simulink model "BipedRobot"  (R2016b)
settings: Solver=ode15s  StartTime=0.0  StopTime=Tend  FixedStep=0.001  RelTol=1e-3  AbsTol=1e-4  EnableMultiTasking=on
PreLoadFcn:
  | BipedRobot_param
  | load walk_forward
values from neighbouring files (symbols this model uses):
  bn = 50    [BipedRobot_param.m]    (also in SimpleContact_param.m)
  bt = 50    [BipedRobot_param.m]    (also in SimpleContact_param.m)
  kn = 5000    [BipedRobot_param.m]    (also in SimpleContact_param.m)
  kt = 5000    [BipedRobot_param.m]    (also in SimpleContact_param.m)
  mu_d = 0.8    [BipedRobot_param.m]    (also in SimpleContact_param.m)
  mu_s = 2    [BipedRobot_param.m]    (also in SimpleContact_param.m)
  N = 100    [initialize_para.m]    (also in main.m = walk_para.N; walk_parameter.m = 5)
  s = robot_para.s    [kinematics_calc.m]    (also in plot_graph.m; robot_parameter.m = 40; robot_view.m)
  zvt = 1e-3    (= 0.001)    [BipedRobot_param.m]    (also in SimpleContact_param.m)
undefined symbols (not defined in the file or in its folder): deg, Inertia, kg, m, Mass
libraries: mblibv1 x89, simulink x1
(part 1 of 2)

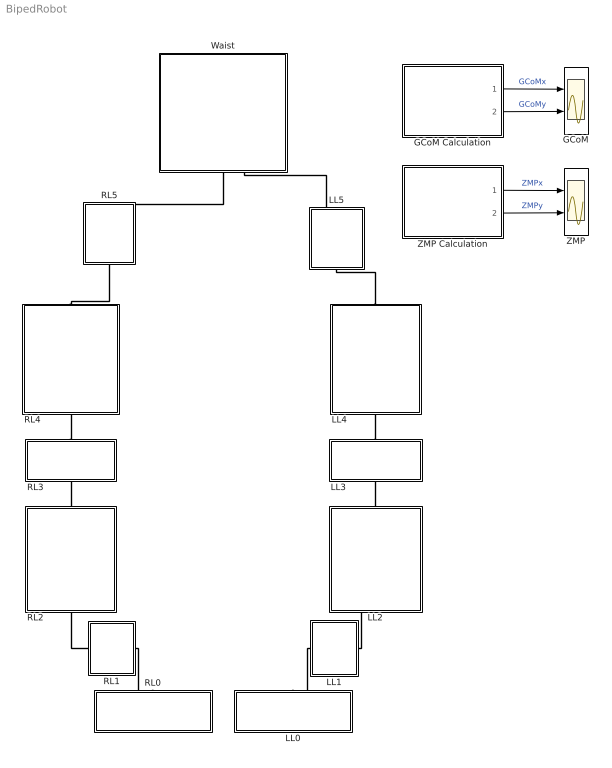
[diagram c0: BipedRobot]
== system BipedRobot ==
  GCoM : Scope  NumInputPorts=2
  GCoM Calculation : Subsystem
  LL0 : Subsystem
  LL1 : Subsystem
  LL2 : Subsystem
  LL3 : Subsystem
  LL4 : Subsystem
  LL5 : Subsystem
  RL0 : Subsystem
  RL1 : Subsystem
  RL2 : Subsystem
  RL3 : Subsystem
  RL4 : Subsystem
  RL5 : Subsystem
  Waist : Subsystem
  ZMP : Scope  NumInputPorts=2
  ZMP Calculation : Subsystem
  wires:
  GCoM Calculation/1(GCoMx) -> GCoM/1  "GCoMx"
  GCoM Calculation/2(GCoMy) -> GCoM/2  "GCoMy"
  ZMP Calculation/1(ZMPx) -> ZMP/1  "ZMPx"
  ZMP Calculation/2(ZMPy) -> ZMP/2  "ZMPy"
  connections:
  RL1/LConn1 -- RL0/RConn1
  RL2/LConn1 -- RL1/RConn1
  RL3/LConn1 -- RL2/RConn1
  Waist/LConn1 -- RL5/RConn1
  LL3/RConn1 -- LL4/LConn1
  LL2/RConn1 -- LL3/LConn1
  LL1/RConn1 -- LL2/LConn1
  LL1/LConn1 -- LL0/RConn1
  RL3/RConn1 -- RL4/LConn1
  RL4/RConn1 -- RL5/LConn1
  Waist/LConn2 -- LL5/RConn1
  LL5/LConn1 -- LL4/RConn1

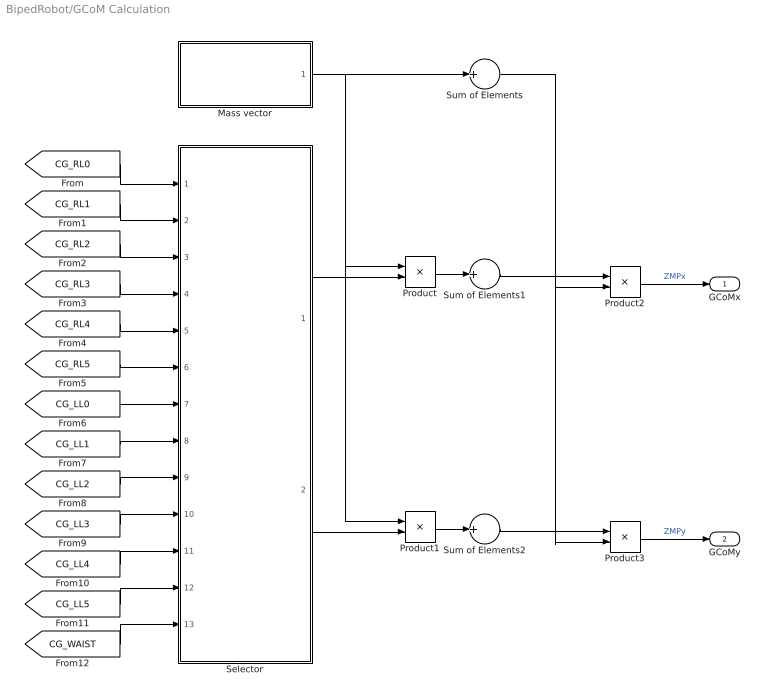
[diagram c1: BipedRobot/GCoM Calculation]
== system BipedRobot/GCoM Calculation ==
  Mass vector : Subsystem
  Product : Product
  Product1 : Product
  Product2 : Product  Inputs=*/
  Product3 : Product  Inputs=*/
  Selector : Subsystem
  Sum of Elements : Sum  Inputs=+
  Sum of Elements1 : Sum  Inputs=+
  Sum of Elements2 : Sum  Inputs=+
  GCoMx : Outport
  GCoMy : Outport  Port=2
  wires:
  Product3/1 -> GCoMy/1  "ZMPy"
  Product2/1 -> GCoMx/1  "ZMPx"
  Product1/1 -> Sum of Elements2/1
  Product/1 -> Sum of Elements1/1
  [CG_RL0] -> Selector/1(CG_RL0)
  [CG_RL1] -> Selector/2(CG_RL1)
  [CG_RL2] -> Selector/3(CG_RL2)
  [CG_RL3] -> Selector/4(CG_RL3)
  [CG_RL4] -> Selector/5(CG_RL4)
  [CG_RL5] -> Selector/6(CG_RL5)
  [CG_LL0] -> Selector/7(CG_LL0)
  [CG_LL1] -> Selector/8(CG_LL1)
  [CG_LL2] -> Selector/9(CG_LL2)
  [CG_LL3] -> Selector/10(CG_LL3)
  [CG_LL4] -> Selector/11(CG_LL4)
  [CG_LL5] -> Selector/12(CG_LL5)
  [CG_WAIST] -> Selector/13(CG_WAIST)
  Selector/2(yvec) -> Product1/2
  Selector/1(xvec) -> Product/2
  Mass vector/1(Mvec) -> Product/1, Product1/1, Sum of Elements/1
  Sum of Elements1/1 -> Product2/1
  Sum of Elements2/1 -> Product3/1
  Sum of Elements/1 -> Product2/2, Product3/2

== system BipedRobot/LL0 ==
  Body : mblibv1/Bodies/Body  LConnTagsString=CS3|CS4|CS5|CS6  RConnTagsString=CG|CS2  UpdateFromCAD=off  DialogClass=MechanicalBodyBlock  Mass=Mass.LL0  MassUnits=kg  InertiaUnits=kg*m^2  Inertia=Inertia.LL0  Shape=Cylinder  ShapeDims=[1 1]  ShapeUnits=m  ShapeUse=false  Density=1  DensityUnits=kg/m^3  DensityUse=false  GraphicsMode=MACHINE_DEFAULT  BodyColorSelMode=MACHINE_DEFAULT  BodyColor=[1;0;0]  AttachedToCS=CG  CG=Right$CG$[7.96 5.62 -13.41]$CS1$CS1$mm$[0 0 0]$Euler X-Y-Z$deg$WORLD$true  WorkingFrames=Left$CS1$[0 20 40]$WORLD$WORLD$mm$[0 0 0]$Euler X-Y-Z$deg$WORLD$false#Right$CS2$[0 0 0]$CS1$CS1$mm$[0 0 0]$Euler X-Y-Z$deg$WORLD$true#Left$CS3$[65 -12.5 -40]$CS1$CS1$mm$[0 0 0]$Euler X-Y-Z$deg$WORLD$true#Left$CS4$[-30 -12.5 -40]$CS1$CS1$mm$[0 0 0]$Euler X-Y-Z$deg$WORLD$true#Left$CS5$[65 52.5 -40]$CS1$CS1$mm$[0 0 0]$Euler X-Y-Z$deg$WORLD$true#Left$CS6$[-30 52.5 -40]$CS1$CS1$mm$[0 0 0]$Euler X-Y-Z$d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  CGPos=[7.96 5.62 -13.41]  CGRot=[0 0 0]  CS0Pos=[]  CS0Rot=[]  CS1Pos=[0 20 40]  CS1Rot=[0 0 0]  CS2Pos=[0 0 0]  CS2Rot=[0 0 0]  CS3Pos=[65 -12.5 -40]  CS3Rot=[0 0 0]  CS4Pos=[-30 -12.5 -40]  CS4Rot=[0 0 0]  CS5Pos=[65 52.5 -40]  CS5Rot=[0 0 0]  CS6Pos=[-30 52.5 -40]  CS6Rot=[0 0 0]  CS7Pos=[]  CS7Rot=[]  CS8Pos=[]  CS8Rot=[]  CS9Pos=[]  CS9Rot=[]  CS10Pos=[]  CS10Rot=[]  CS11Pos=[]  CS11Rot=[]  CS12Pos=[]  CS12Rot=[]  CS13Pos=[]  CS13Rot=[]  CS14Pos=[]  CS14Rot=[]  CS15Pos=[]  CS15Rot=[]  CS16Pos=[]  CS16Rot=[]  CS17Pos=[]  CS17Rot=[]  CS18Pos=[]  CS18Rot=[]  CS19Pos=[]  CS19Rot=[]  CS20Pos=[]  CS20Rot=[]
  Body Sensor : mblibv1/Sensors &  Actuators/Body Sensor  UpdateFromCAD=off  PhysicalDomain=Mechanical  PortType=blob  Muxed=off  Pose=off  Angle=on  AngleUnits=deg  ArcVelocity=off  ArcVelocityUnits=deg/s  ArcAcceleration=off  ArcAccelerationUnits=deg/s^2  CoordPosition=on  CoordPositionUnits=m  Velocity=off  VelocityUnits=m/s  Acceleration=off  AccelerationUnits=m/s^2  Quaternion=on  QuaternionDT=off  QuaternionDDT=off  QuaternionUnits=off  OutputVector=[1]  ActiveIO=on  Width=3  DialogClass=MechanicalSensorBlock  ReferenceFrame=Absolute (World)
  Contact1 : Subsystem
  Contact2 : Subsystem
  Contact3 : Subsystem
  Contact4 : Subsystem
  From Workspace : FromWorkspace  VariableName=Motion.LL0  SampleTime=0
  Joint Actuator : mblibv1/Sensors &  Actuators/Joint Actuator  UpdateFromCAD=off  PhysicalDomain=Mechanical  PortType=blob  ActuationStyle=Motion  AngleUnits=deg  ArcVelocityUnits=deg/s  ArcAccelerationUnits=deg/s^2  CoordPositionUnits=m  VelocityUnits=m/s  AccelerationUnits=m/s^2  ForceUnits=N  TorqueUnits=N-m  ActiveIO=on  Width=3  DialogClass=MechanicalActuatorBlock  Primitive=R1  ReferenceFrame=Absolute (INERTIAL)
  Mechanical Branching Bar : mblibv1/Utilities/Mechanical Branching Bar  LConnTagsString=_newl0  RConnTagsString=SA0|SA1  UpdateFromCAD=off  DialogClass=MechanicalBranchingBarBlock  NumSAPorts=2
  Revolute : mblibv1/Joints/Revolute  LConnTagsString=__newl0|SA1  RConnTagsString=__newr0  UpdateFromCAD=off  NumSAPorts=1  CutJoint=off  MarkAsCut=off  Primitives=revolute  PrimitiveProps=R1$World$[1 0 0]$revolute  DialogClass=JointBlock  R1Axis=[1 0 0]
  C1 : PMIOPort  Port=1  Side=Right
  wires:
  From Workspace/1 -> Joint Actuator/1
  Body Sensor/1 -> [CG_LL0]
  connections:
  Contact1/RConn1 -- Body/LConn1
  Contact2/RConn1 -- Body/LConn2
  Contact3/RConn1 -- Body/LConn3
  Contact4/RConn1 -- Body/LConn4
  C1/RConn1 -- Revolute/RConn1
  Mechanical Branching Bar/LConn1 -- Revolute/LConn2
  Joint Actuator/RConn1 -- Mechanical Branching Bar/RConn1
  Revolute/LConn1 -- Body/RConn2
  Body Sensor/LConn1 -- Body/RConn1

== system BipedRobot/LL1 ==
  Body : mblibv1/Bodies/Body  LConnTagsString=CG|CS1  RConnTagsString=CS2  UpdateFromCAD=off  DialogClass=MechanicalBodyBlock  Mass=Mass.LL1  MassUnits=kg  InertiaUnits=kg*m^2  Inertia=Inertia.LL1  Shape=Cylinder  ShapeDims=[1 1]  ShapeUnits=m  ShapeUse=false  Density=1  DensityUnits=kg/m^3  DensityUse=false  GraphicsMode=MACHINE_DEFAULT  BodyColorSelMode=MACHINE_DEFAULT  BodyColor=[1;0;0]  AttachedToCS=CG  CG=Left$CG$[-6.4 13.1 0]$CS1$CS1$mm$[0 0 0]$Euler X-Y-Z$deg$WORLD$true  WorkingFrames=Left$CS1$[0 20 40]$WORLD$WORLD$mm$[0 0 0]$Euler X-Y-Z$deg$WORLD$true#Right$CS2$[0 0 0]$CS1$CS1$mm$[0 0 0]$Euler X-Y-Z$deg$WORLD$true  CGPos=[-6.4 13.1 0]  CGRot=[0 0 0]  CS0Pos=[]  CS0Rot=[]  CS1Pos=[0 20 40]  CS1Rot=[0 0 0]  CS2Pos=[0 0 0]  CS2Rot=[0 0 0]  CS3Pos=[]  CS3Rot=[]  CS4Pos=[]  CS4Rot=[]  CS5Pos=[]  CS5Rot=[]  CS6Pos=[]  CS6Rot=[]  CS7Pos=[]  CS7Rot=[]  CS8Pos=[]  CS8Rot=[]  CS9Pos=[]  CS9Rot=[]  CS10Pos=[]  CS10Rot=[]  CS11Pos=[]  CS11Rot=[]  CS12Pos=[]  CS12Rot=[]  CS13Pos=[]  CS13Rot=[]  CS14Pos=[]  CS14Rot=[]  CS15Pos=[]  CS15Rot=[]  CS16Pos=[]  CS16Rot=[]  CS17Pos=[]  CS17Rot=[]  CS18Pos=[]  CS18Rot=[]  CS19Pos=[]  CS19Rot=[]  CS20Pos=[]  CS20Rot=[]
  Body Sensor : mblibv1/Sensors &  Actuators/Body Sensor  UpdateFromCAD=off  PhysicalDomain=Mechanical  PortType=blob  Muxed=off  Pose=off  Angle=on  AngleUnits=deg  ArcVelocity=off  ArcVelocityUnits=deg/s  ArcAcceleration=off  ArcAccelerationUnits=deg/s^2  CoordPosition=on  CoordPositionUnits=m  Velocity=off  VelocityUnits=m/s  Acceleration=off  AccelerationUnits=m/s^2  Quaternion=on  QuaternionDT=off  QuaternionDDT=off  QuaternionUnits=off  OutputVector=[1]  ActiveIO=on  Width=3  DialogClass=MechanicalSensorBlock  ReferenceFrame=Absolute (World)
  From Workspace : FromWorkspace  VariableName=Motion.LL1  SampleTime=0
  Joint Actuator : mblibv1/Sensors &  Actuators/Joint Actuator  UpdateFromCAD=off  PhysicalDomain=Mechanical  PortType=blob  ActuationStyle=Motion  AngleUnits=deg  ArcVelocityUnits=deg/s  ArcAccelerationUnits=deg/s^2  CoordPositionUnits=m  VelocityUnits=m/s  AccelerationUnits=m/s^2  ForceUnits=N  TorqueUnits=N-m  ActiveIO=on  Width=3  DialogClass=MechanicalActuatorBlock  Primitive=R1  ReferenceFrame=Absolute (INERTIAL)
  Mechanical Branching Bar : mblibv1/Utilities/Mechanical Branching Bar  LConnTagsString=_newl0  RConnTagsString=SA0|SA1  UpdateFromCAD=off  DialogClass=MechanicalBranchingBarBlock  NumSAPorts=2
  Revolute : mblibv1/Joints/Revolute  LConnTagsString=__newl0|SA1  RConnTagsString=__newr0  UpdateFromCAD=off  NumSAPorts=1  CutJoint=off  MarkAsCut=off  Primitives=revolute  PrimitiveProps=R1$WORLD$[0 -1 0]$revolute  DialogClass=JointBlock  R1Axis=[0 -1 0]
  C1 : PMIOPort  Port=1  Side=Right
  C2 : PMIOPort  Port=2  Side=Left
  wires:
  From Workspace/1 -> Joint Actuator/1
  Body Sensor/1 -> [CG_LL1]
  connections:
  Body/LConn2 -- C2/RConn1
  Revolute/LConn1 -- Body/RConn1
  Revolute/RConn1 -- C1/RConn1
  Joint Actuator/RConn1 -- Mechanical Branching Bar/RConn1
  Mechanical Branching Bar/LConn1 -- Revolute/LConn2
  Body Sensor/LConn1 -- Body/LConn1

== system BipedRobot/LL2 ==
  Body : mblibv1/Bodies/Body  LConnTagsString=CG|CS1  RConnTagsString=CS2  UpdateFromCAD=off  DialogClass=MechanicalBodyBlock  Mass=Mass.LL2  MassUnits=kg  InertiaUnits=kg*m^2  Inertia=Inertia.LL2  Shape=Cylinder  ShapeDims=[1 1]  ShapeUnits=m  ShapeUse=false  Density=1  DensityUnits=kg/m^3  DensityUse=false  GraphicsMode=MACHINE_DEFAULT  BodyColorSelMode=MACHINE_DEFAULT  BodyColor=[1;0;0]  AttachedToCS=CG  CG=Left$CG$[10.55 32.59 38.17]$CS1$CS1$mm$[0 0 0]$Euler X-Y-Z$deg$WORLD$true  WorkingFrames=Left$CS1$[0 20 40]$WORLD$WORLD$mm$[0 0 0]$Euler X-Y-Z$deg$WORLD$true#Right$CS2$[0 0 85]$CS1$CS1$mm$[0 0 0]$Euler X-Y-Z$deg$WORLD$true  CGPos=[10.55 32.59 38.17]  CGRot=[0 0 0]  CS0Pos=[]  CS0Rot=[]  CS1Pos=[0 20 40]  CS1Rot=[0 0 0]  CS2Pos=[0 0 85]  CS2Rot=[0 0 0]  CS3Pos=[]  CS3Rot=[]  CS4Pos=[]  CS4Rot=[]  CS5Pos=[]  CS5Rot=[]  CS6Pos=[]  CS6Rot=[]  CS7Pos=[]  CS7Rot=[]  CS8Pos=[]  CS8Rot=[]  CS9Pos=[]  CS9Rot=[]  CS10Pos=[]  CS10Rot=[]  CS11Pos=[]  CS11Rot=[]  CS12Pos=[]  CS12Rot=[]  CS13Pos=[]  CS13Rot=[]  CS14Pos=[]  CS14Rot=[]  CS15Pos=[]  CS15Rot=[]  CS16Pos=[]  CS16Rot=[]  CS17Pos=[]  CS17Rot=[]  CS18Pos=[]  CS18Rot=[]  CS19Pos=[]  CS19Rot=[]  CS20Pos=[]  CS20Rot=[]
  Body Sensor : mblibv1/Sensors &  Actuators/Body Sensor  UpdateFromCAD=off  PhysicalDomain=Mechanical  PortType=blob  Muxed=off  Pose=off  Angle=on  AngleUnits=deg  ArcVelocity=off  ArcVelocityUnits=deg/s  ArcAcceleration=off  ArcAccelerationUnits=deg/s^2  CoordPosition=on  CoordPositionUnits=m  Velocity=off  VelocityUnits=m/s  Acceleration=off  AccelerationUnits=m/s^2  Quaternion=on  QuaternionDT=off  QuaternionDDT=off  QuaternionUnits=off  OutputVector=[1]  ActiveIO=on  Width=3  DialogClass=MechanicalSensorBlock  ReferenceFrame=Absolute (World)
  From Workspace : FromWorkspace  VariableName=Motion.LL2  SampleTime=0
  Joint Actuator : mblibv1/Sensors &  Actuators/Joint Actuator  UpdateFromCAD=off  PhysicalDomain=Mechanical  PortType=blob  ActuationStyle=Motion  AngleUnits=deg  ArcVelocityUnits=deg/s  ArcAccelerationUnits=deg/s^2  CoordPositionUnits=m  VelocityUnits=m/s  AccelerationUnits=m/s^2  ForceUnits=N  TorqueUnits=N-m  ActiveIO=on  Width=3  DialogClass=MechanicalActuatorBlock  Primitive=R1  ReferenceFrame=Absolute (INERTIAL)
  Mechanical Branching Bar : mblibv1/Utilities/Mechanical Branching Bar  LConnTagsString=_newl0  RConnTagsString=SA0|SA1  UpdateFromCAD=off  DialogClass=MechanicalBranchingBarBlock  NumSAPorts=2
  Revolute : mblibv1/Joints/Revolute  LConnTagsString=__newl0|SA1  RConnTagsString=__newr0  UpdateFromCAD=off  NumSAPorts=1  CutJoint=off  MarkAsCut=off  Primitives=revolute  PrimitiveProps=R1$WORLD$[0 -1 0]$revolute  DialogClass=JointBlock  R1Axis=[0 -1 0]
  C1 : PMIOPort  Port=1  Side=Right
  C2 : PMIOPort  Port=2  Side=Left
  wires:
  From Workspace/1 -> Joint Actuator/1
  Body Sensor/1 -> [CG_LL2]
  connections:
  Body/LConn2 -- C2/RConn1
  Body/RConn1 -- Revolute/LConn1
  Revolute/RConn1 -- C1/RConn1
  Joint Actuator/RConn1 -- Mechanical Branching Bar/RConn1
  Mechanical Branching Bar/LConn1 -- Revolute/LConn2
  Body Sensor/LConn1 -- Body/LConn1

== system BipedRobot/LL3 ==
  Body : mblibv1/Bodies/Body  LConnTagsString=CG|CS2  RConnTagsString=CS1  UpdateFromCAD=off  DialogClass=MechanicalBodyBlock  Mass=Mass.LL3  MassUnits=kg  InertiaUnits=kg*m^2  Inertia=Inertia.LL3  Shape=Cylinder  ShapeDims=[1 1]  ShapeUnits=m  ShapeUse=false  Density=1  DensityUnits=kg/m^3  DensityUse=false  GraphicsMode=MACHINE_DEFAULT  BodyColorSelMode=MACHINE_DEFAULT  BodyColor=[1;0;0]  AttachedToCS=CG  CG=Left$CG$[7.6 30.24 -48.36]$CS1$CS1$mm$[0 0 0]$Euler X-Y-Z$deg$WORLD$true  WorkingFrames=Right$CS1$[0 20 210]$WORLD$WORLD$mm$[0 0 0]$Euler X-Y-Z$deg$WORLD$true#Left$CS2$[0 0 -85]$CS1$CS1$mm$[0 0 0]$Euler X-Y-Z$deg$WORLD$true  CGPos=[7.6 30.24 -48.36]  CGRot=[0 0 0]  CS0Pos=[]  CS0Rot=[]  CS1Pos=[0 20 210]  CS1Rot=[0 0 0]  CS2Pos=[0 0 -85]  CS2Rot=[0 0 0]  CS3Pos=[]  CS3Rot=[]  CS4Pos=[]  CS4Rot=[]  CS5Pos=[]  CS5Rot=[]  CS6Pos=[]  CS6Rot=[]  CS7Pos=[]  CS7Rot=[]  CS8Pos=[]  CS8Rot=[]  CS9Pos=[]  CS9Rot=[]  CS10Pos=[]  CS10Rot=[]  CS11Pos=[]  CS11Rot=[]  CS12Pos=[]  CS12Rot=[]  CS13Pos=[]  CS13Rot=[]  CS14Pos=[]  CS14Rot=[]  CS15Pos=[]  CS15Rot=[]  CS16Pos=[]  CS16Rot=[]  CS17Pos=[]  CS17Rot=[]  CS18Pos=[]  CS18Rot=[]  CS19Pos=[]  CS19Rot=[]  CS20Pos=[]  CS20Rot=[]
  Body Sensor : mblibv1/Sensors &  Actuators/Body Sensor  UpdateFromCAD=off  PhysicalDomain=Mechanical  PortType=blob  Muxed=off  Pose=off  Angle=on  AngleUnits=deg  ArcVelocity=off  ArcVelocityUnits=deg/s  ArcAcceleration=off  ArcAccelerationUnits=deg/s^2  CoordPosition=on  CoordPositionUnits=m  Velocity=off  VelocityUnits=m/s  Acceleration=off  AccelerationUnits=m/s^2  Quaternion=on  QuaternionDT=off  QuaternionDDT=off  QuaternionUnits=off  OutputVector=[1]  ActiveIO=on  Width=3  DialogClass=MechanicalSensorBlock  ReferenceFrame=Absolute (World)
  From Workspace : FromWorkspace  VariableName=Motion.LL3  SampleTime=0
  Joint Actuator : mblibv1/Sensors &  Actuators/Joint Actuator  UpdateFromCAD=off  PhysicalDomain=Mechanical  PortType=blob  ActuationStyle=Motion  AngleUnits=deg  ArcVelocityUnits=deg/s  ArcAccelerationUnits=deg/s^2  CoordPositionUnits=m  VelocityUnits=m/s  AccelerationUnits=m/s^2  ForceUnits=N  TorqueUnits=N-m  ActiveIO=on  Width=3  DialogClass=MechanicalActuatorBlock  Primitive=R1  ReferenceFrame=Absolute (INERTIAL)
  Mechanical Branching Bar : mblibv1/Utilities/Mechanical Branching Bar  LConnTagsString=_newl0  RConnTagsString=SA0|SA1  UpdateFromCAD=off  DialogClass=MechanicalBranchingBarBlock  NumSAPorts=2
  Revolute : mblibv1/Joints/Revolute  LConnTagsString=__newl0|SA1  RConnTagsString=__newr0  UpdateFromCAD=off  NumSAPorts=1  CutJoint=off  MarkAsCut=off  Primitives=revolute  PrimitiveProps=R1$WORLD$[0 -1 0]$revolute  DialogClass=JointBlock  R1Axis=[0 -1 0]
  C1 : PMIOPort  Port=1  Side=Right
  C2 : PMIOPort  Port=2  Side=Left
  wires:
  From Workspace/1 -> Joint Actuator/1
  Body Sensor/1 -> [CG_LL3]
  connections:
  Body/LConn2 -- C2/RConn1
  Body/RConn1 -- Revolute/LConn1
  Revolute/RConn1 -- C1/RConn1
  Joint Actuator/RConn1 -- Mechanical Branching Bar/RConn1
  Mechanical Branching Bar/LConn1 -- Revolute/LConn2
  Body Sensor/LConn1 -- Body/LConn1

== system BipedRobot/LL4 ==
  Body : mblibv1/Bodies/Body  LConnTagsString=CS1  RConnTagsString=CG|CS2  UpdateFromCAD=off  DialogClass=MechanicalBodyBlock  Mass=Mass.LL4  MassUnits=kg  InertiaUnits=kg*m^2  Inertia=Inertia.LL4  Shape=Cylinder  ShapeDims=[1 1]  ShapeUnits=m  ShapeUse=false  Density=1  DensityUnits=kg/m^3  DensityUse=false  GraphicsMode=MACHINE_DEFAULT  BodyColorSelMode=MACHINE_DEFAULT  BodyColor=[1;0;0]  AttachedToCS=CG  CG=Right$CG$[22.94 16.61 0]$CS1$CS1$mm$[0 0 0]$Euler X-Y-Z$deg$WORLD$true  WorkingFrames=Left$CS1$[0 20 210]$WORLD$WORLD$mm$[0 0 0]$Euler X-Y-Z$deg$WORLD$true#Right$CS2$[0 0 0]$CS1$CS1$mm$[0 0 0]$Euler X-Y-Z$deg$WORLD$true  CGPos=[22.94 16.61 0]  CGRot=[0 0 0]  CS0Pos=[]  CS0Rot=[]  CS1Pos=[0 20 210]  CS1Rot=[0 0 0]  CS2Pos=[0 0 0]  CS2Rot=[0 0 0]  CS3Pos=[]  CS3Rot=[]  CS4Pos=[]  CS4Rot=[]  CS5Pos=[]  CS5Rot=[]  CS6Pos=[]  CS6Rot=[]  CS7Pos=[]  CS7Rot=[]  CS8Pos=[]  CS8Rot=[]  CS9Pos=[]  CS9Rot=[]  CS10Pos=[]  CS10Rot=[]  CS11Pos=[]  CS11Rot=[]  CS12Pos=[]  CS12Rot=[]  CS13Pos=[]  CS13Rot=[]  CS14Pos=[]  CS14Rot=[]  CS15Pos=[]  CS15Rot=[]  CS16Pos=[]  CS16Rot=[]  CS17Pos=[]  CS17Rot=[]  CS18Pos=[]  CS18Rot=[]  CS19Pos=[]  CS19Rot=[]  CS20Pos=[]  CS20Rot=[]
  Body Sensor : mblibv1/Sensors &  Actuators/Body Sensor  UpdateFromCAD=off  PhysicalDomain=Mechanical  PortType=blob  Muxed=off  Pose=off  Angle=on  AngleUnits=deg  ArcVelocity=off  ArcVelocityUnits=deg/s  ArcAcceleration=off  ArcAccelerationUnits=deg/s^2  CoordPosition=on  CoordPositionUnits=m  Velocity=off  VelocityUnits=m/s  Acceleration=off  AccelerationUnits=m/s^2  Quaternion=on  QuaternionDT=off  QuaternionDDT=off  QuaternionUnits=off  OutputVector=[1]  ActiveIO=on  Width=3  DialogClass=MechanicalSensorBlock  ReferenceFrame=Absolute (World)
  From Workspace : FromWorkspace  VariableName=Motion.LL4  SampleTime=0
  Joint Actuator : mblibv1/Sensors &  Actuators/Joint Actuator  UpdateFromCAD=off  PhysicalDomain=Mechanical  PortType=blob  ActuationStyle=Motion  AngleUnits=deg  ArcVelocityUnits=deg/s  ArcAccelerationUnits=deg/s^2  CoordPositionUnits=m  VelocityUnits=m/s  AccelerationUnits=m/s^2  ForceUnits=N  TorqueUnits=N-m  ActiveIO=on  Width=3  DialogClass=MechanicalActuatorBlock  Primitive=R1  ReferenceFrame=Absolute (INERTIAL)
  Mechanical Branching Bar : mblibv1/Utilities/Mechanical Branching Bar  LConnTagsString=_newl0  RConnTagsString=SA0|SA1  UpdateFromCAD=off  DialogClass=MechanicalBranchingBarBlock  NumSAPorts=2
  Revolute : mblibv1/Joints/Revolute  LConnTagsString=__newl0|SA1  RConnTagsString=__newr0  UpdateFromCAD=off  NumSAPorts=1  CutJoint=off  MarkAsCut=off  Primitives=revolute  PrimitiveProps=R1$WORLD$[1 0 0]$revolute  DialogClass=JointBlock  R1Axis=[1 0 0]
  C2 : PMIOPort  Port=1  Side=Left
  C1 : PMIOPort  Port=2  Side=Right
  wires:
  From Workspace/1 -> Joint Actuator/1
  Body Sensor/1 -> [CG_LL4]
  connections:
  C2/RConn1 -- Body/RConn2
  Revolute/LConn1 -- Body/LConn1
  Revolute/RConn1 -- C1/RConn1
  Mechanical Branching Bar/RConn1 -- Joint Actuator/RConn1
  Mechanical Branching Bar/LConn1 -- Revolute/LConn2
  Body Sensor/LConn1 -- Body/RConn1

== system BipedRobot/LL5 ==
  Body : mblibv1/Bodies/Body  LConnTagsString=CG|CS1  RConnTagsString=CS2  UpdateFromCAD=off  DialogClass=MechanicalBodyBlock  Mass=Mass.LL5  MassUnits=kg  InertiaUnits=kg*m^2  Inertia=Inertia.LL5  Shape=Cylinder  ShapeDims=[1 1]  ShapeUnits=m  ShapeUse=false  Density=1  DensityUnits=kg/m^3  DensityUse=false  GraphicsMode=MACHINE_DEFAULT  BodyColorSelMode=MACHINE_DEFAULT  BodyColor=[1;0;0]  AttachedToCS=CG  CG=Left$CG$[7.11 0 5.09]$CS1$CS1$mm$[0 0 0]$Euler X-Y-Z$deg$WORLD$true  WorkingFrames=Left$CS1$[0 20 210]$WORLD$WORLD$mm$[0 0 0]$Euler X-Y-Z$deg$WORLD$true#Right$CS2$[0 0 0]$CS1$CS1$mm$[0 0 0]$Euler X-Y-Z$deg$WORLD$true  CGPos=[7.11 0 5.09]  CGRot=[0 0 0]  CS0Pos=[]  CS0Rot=[]  CS1Pos=[0 20 210]  CS1Rot=[0 0 0]  CS2Pos=[0 0 0]  CS2Rot=[0 0 0]  CS3Pos=[]  CS3Rot=[]  CS4Pos=[]  CS4Rot=[]  CS5Pos=[]  CS5Rot=[]  CS6Pos=[]  CS6Rot=[]  CS7Pos=[]  CS7Rot=[]  CS8Pos=[]  CS8Rot=[]  CS9Pos=[]  CS9Rot=[]  CS10Pos=[]  CS10Rot=[]  CS11Pos=[]  CS11Rot=[]  CS12Pos=[]  CS12Rot=[]  CS13Pos=[]  CS13Rot=[]  CS14Pos=[]  CS14Rot=[]  CS15Pos=[]  CS15Rot=[]  CS16Pos=[]  CS16Rot=[]  CS17Pos=[]  CS17Rot=[]  CS18Pos=[]  CS18Rot=[]  CS19Pos=[]  CS19Rot=[]  CS20Pos=[]  CS20Rot=[]
  Body Sensor : mblibv1/Sensors &  Actuators/Body Sensor  UpdateFromCAD=off  PhysicalDomain=Mechanical  PortType=blob  Muxed=off  Pose=off  Angle=on  AngleUnits=deg  ArcVelocity=off  ArcVelocityUnits=deg/s  ArcAcceleration=off  ArcAccelerationUnits=deg/s^2  CoordPosition=on  CoordPositionUnits=m  Velocity=off  VelocityUnits=m/s  Acceleration=off  AccelerationUnits=m/s^2  Quaternion=on  QuaternionDT=off  QuaternionDDT=off  QuaternionUnits=off  OutputVector=[1]  ActiveIO=on  Width=3  DialogClass=MechanicalSensorBlock  ReferenceFrame=Absolute (World)
  From Workspace : FromWorkspace  VariableName=Motion.LL5  SampleTime=0
  Joint Actuator : mblibv1/Sensors &  Actuators/Joint Actuator  UpdateFromCAD=off  PhysicalDomain=Mechanical  PortType=blob  ActuationStyle=Motion  AngleUnits=deg  ArcVelocityUnits=deg/s  ArcAccelerationUnits=deg/s^2  CoordPositionUnits=m  VelocityUnits=m/s  AccelerationUnits=m/s^2  ForceUnits=N  TorqueUnits=N-m  ActiveIO=on  Width=3  DialogClass=MechanicalActuatorBlock  Primitive=R1  ReferenceFrame=Absolute (INERTIAL)
  Mechanical Branching Bar : mblibv1/Utilities/Mechanical Branching Bar  LConnTagsString=_newl0  RConnTagsString=SA0|SA1  UpdateFromCAD=off  DialogClass=MechanicalBranchingBarBlock  NumSAPorts=2
  Revolute : mblibv1/Joints/Revolute  LConnTagsString=__newl0|SA1  RConnTagsString=__newr0  UpdateFromCAD=off  NumSAPorts=1  CutJoint=off  MarkAsCut=off  Primitives=revolute  PrimitiveProps=R1$World$[0 0 1]$revolute  DialogClass=JointBlock  R1Axis=[0 0 1]
  C1 : PMIOPort  Port=1  Side=Right
  C2 : PMIOPort  Port=2  Side=Left
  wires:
  From Workspace/1 -> Joint Actuator/1
  Body Sensor/1 -> [CG_LL5]
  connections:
  C2/RConn1 -- Body/LConn2
  Revolute/LConn1 -- Body/RConn1
  Revolute/RConn1 -- C1/RConn1
  Mechanical Branching Bar/RConn1 -- Joint Actuator/RConn1
  Mechanical Branching Bar/LConn1 -- Revolute/LConn2
  Body Sensor/LConn1 -- Body/LConn1

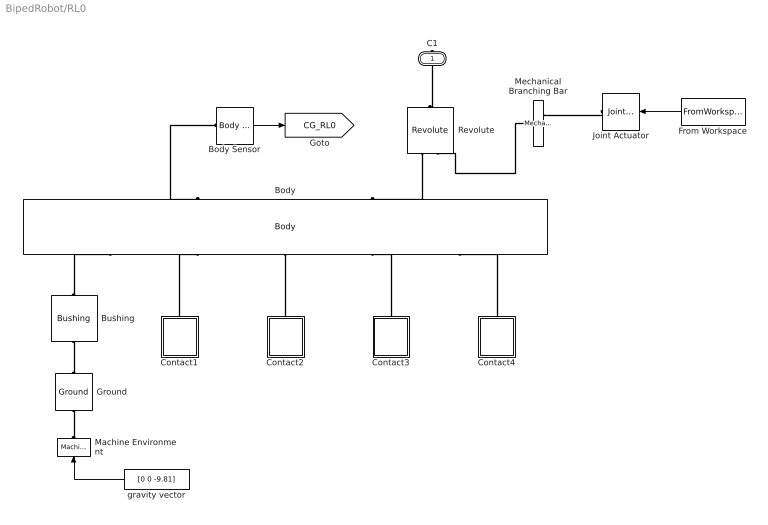
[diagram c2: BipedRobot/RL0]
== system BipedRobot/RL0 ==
  Body : mblibv1/Bodies/Body  LConnTagsString=CS1|CS3|CS4|CS5|CS6  RConnTagsString=CG|CS2  UpdateFromCAD=off  DialogClass=MechanicalBodyBlock  Mass=Mass.RL0  MassUnits=kg  InertiaUnits=kg*m^2  Inertia=Inertia.RL0  Shape=Cylinder  ShapeDims=[1 1]  ShapeUnits=m  ShapeUse=false  Density=1  DensityUnits=kg/m^3  DensityUse=false  GraphicsMode=MACHINE_DEFAULT  BodyColorSelMode=MACHINE_DEFAULT  BodyColor=[1;0;0]  AttachedToCS=CG  CG=Right$CG$[7.96 -5.62 -13.41]$CS1$CS1$mm$[0 0 0]$Euler X-Y-Z$deg$WORLD$true  WorkingFrames=Left$CS1$[0 -20 40]$WORLD$WORLD$mm$[0 0 0]$Euler X-Y-Z$deg$WORLD$true#Right$CS2$[0 0 0]$CS1$CS1$mm$[0 0 0]$Euler X-Y-Z$deg$WORLD$true#Left$CS3$[65 12.5 -40]$CS1$CS1$mm$[0 0 0]$Euler X-Y-Z$deg$WORLD$true#Left$CS4$[-30 12.5 -40]$CS1$CS1$mm$[0 0 0]$Euler X-Y-Z$deg$WORLD$true#Left$CS5$[65 -52.5 -40]$CS1$CS1$mm$[0 0 0]$Euler X-Y-Z$deg$WORLD$true#Left$CS6$[-30 -52.5 -40]$CS1$CS1$mm$[0 0 0]$Euler X-Y-Z$d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  CGPos=[7.96 -5.62 -13.41]  CGRot=[0 0 0]  CS0Pos=[]  CS0Rot=[]  CS1Pos=[0 -20 40]  CS1Rot=[0 0 0]  CS2Pos=[0 0 0]  CS2Rot=[0 0 0]  CS3Pos=[65 12.5 -40]  CS3Rot=[0 0 0]  CS4Pos=[-30 12.5 -40]  CS4Rot=[0 0 0]  CS5Pos=[65 -52.5 -40]  CS5Rot=[0 0 0]  CS6Pos=[-30 -52.5 -40]  CS6Rot=[0 0 0]  CS7Pos=[]  CS7Rot=[]  CS8Pos=[]  CS8Rot=[]  CS9Pos=[]  CS9Rot=[]  CS10Pos=[]  CS10Rot=[]  CS11Pos=[]  CS11Rot=[]  CS12Pos=[]  CS12Rot=[]  CS13Pos=[]  CS13Rot=[]  CS14Pos=[]  CS14Rot=[]  CS15Pos=[]  CS15Rot=[]  CS16Pos=[]  CS16Rot=[]  CS17Pos=[]  CS17Rot=[]  CS18Pos=[]  CS18Rot=[]  CS19Pos=[]  CS19Rot=[]  CS20Pos=[]  CS20Rot=[]
  Body Sensor : mblibv1/Sensors &  Actuators/Body Sensor  UpdateFromCAD=off  PhysicalDomain=Mechanical  PortType=blob  Muxed=off  Pose=off  Angle=on  AngleUnits=deg  ArcVelocity=off  ArcVelocityUnits=deg/s  ArcAcceleration=off  ArcAccelerationUnits=deg/s^2  CoordPosition=on  CoordPositionUnits=m  Velocity=off  VelocityUnits=m/s  Acceleration=off  AccelerationUnits=m/s^2  Quaternion=on  QuaternionDT=off  QuaternionDDT=off  QuaternionUnits=off  OutputVector=[1]  ActiveIO=on  Width=3  DialogClass=MechanicalSensorBlock  ReferenceFrame=Absolute (World)
  Bushing : mblibv1/Joints/Bushing  LConnTagsString=__newl0  RConnTagsString=__newr0  UpdateFromCAD=off  NumSAPorts=0  CutJoint=off  MarkAsCut=off  Primitives=prismatic_prismatic_prismatic  PrimitiveProps=P1$WORLD$[1 0 0]$prismatic#P2$WORLD$[0 1 0]$prismatic#P3$WORLD$[0 0 1]$prismatic#R1$WORLD$[1 0 0]$revolute#R2$WORLD$[0 1 0]$revolute#R3$WORLD$[0 0 1]$revolute  DialogClass=JointBlock  P1Axis=[1 0 0]  P2Axis=[0 1 0]  P3Axis=[0 0 1]  R1Axis=[1 0 0]  R2Axis=[0 1 0]  R3Axis=[0 0 1]
  Contact1 : Subsystem
  Contact2 : Subsystem
  Contact3 : Subsystem
  Contact4 : Subsystem
  From Workspace : FromWorkspace  VariableName=Motion.RL0  SampleTime=0
  Ground : mblibv1/Bodies/Ground  UpdateFromCAD=off  LeftPortType=env  RightPortType=workingframe  PhysicalDomain=Mechanical  DialogClass=GroundBlock  CoordPosition=[0 -20 40]  CoordPositionUnits=mm  StateVectorMgrId=-1  MachineId=[0 0]  ShowEnvPort=on  ParameterChecksum=[406545068, 1964465438, 4287204415, 2979037449]  TopologyChecksum=[926443555, 1296550474, 3859835272, 3746694248]
  Joint Actuator : mblibv1/Sensors &  Actuators/Joint Actuator  UpdateFromCAD=off  PhysicalDomain=Mechanical  PortType=blob  ActuationStyle=Motion  AngleUnits=deg  ArcVelocityUnits=deg/s  ArcAccelerationUnits=deg/s^2  CoordPositionUnits=m  VelocityUnits=m/s  AccelerationUnits=m/s^2  ForceUnits=N  TorqueUnits=N-m  ActiveIO=on  Width=3  DialogClass=MechanicalActuatorBlock  Primitive=R1  ReferenceFrame=Absolute (INERTIAL)
  Machine Environment : mblibv1/Bodies/Machine Environment  Tag=Factory ground  PortType=env  PhysicalDomain=Mechanical  DialogTemplateClass=MECH.MachineEnvironment  SyncWhenCopied=off  Gravity=[0 0 9.81]  GravityUnits=m/s^2  GravityAsSignal=on  Dimensionality=Auto-detect  AnalysisType=Forward dynamics  LinearAssemblyTolerance=1e-3  LinearAssemblyToleranceUnits=m  AngularAssemblyTolerance=1e-3  AngularAssemblyToleranceUnits=rad  ConstraintSolverType=Stabilizing  ConstraintRelTolerance=1e-4  ConstraintAbsTolerance=1e-4  UseRobustSingularityHandling=off  RedundancyAnalysisToleranceType=Automatically select tolerance  RedundancyAnalysisTolerance=1e-14  StatePerturbationType=Fixed  PerturbationSize=1e-5  VisualizeMachine=on  BodyVisualizationType=Use model default body geometries  BodyColorSelMode=Use model default  DefaultBodyColor=[1 0 0]
  Mechanical Branching Bar : mblibv1/Utilities/Mechanical Branching Bar  LConnTagsString=_newl0  RConnTagsString=SA0|SA1  UpdateFromCAD=off  DialogClass=MechanicalBranchingBarBlock  NumSAPorts=2
  Revolute : mblibv1/Joints/Revolute  LConnTagsString=__newl0|SA1  RConnTagsString=__newr0  UpdateFromCAD=off  NumSAPorts=1  CutJoint=off  MarkAsCut=off  Primitives=revolute  PrimitiveProps=R1$World$[-1 0 0]$revolute  DialogClass=JointBlock  R1Axis=[-1 0 0]
  gravity vector : Constant  Value=[0 0 -9.81]
  C1 : PMIOPort  Port=1  Side=Right
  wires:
  gravity vector/1 -> Machine Environment/1
  From Workspace/1 -> Joint Actuator/1
  Body Sensor/1 -> [CG_RL0]
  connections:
  Machine Environment/RConn1 -- Ground/LConn1
  Bushing/RConn1 -- Body/LConn1
  Bushing/LConn1 -- Ground/RConn1
  Contact1/RConn1 -- Body/LConn2
  Contact2/RConn1 -- Body/LConn3
  Contact3/RConn1 -- Body/LConn4
  Contact4/RConn1 -- Body/LConn5
  C1/RConn1 -- Revolute/RConn1
  Revolute/LConn1 -- Body/RConn2
  Mechanical Branching Bar/LConn1 -- Revolute/LConn2
  Joint Actuator/RConn1 -- Mechanical Branching Bar/RConn1
  Body Sensor/LConn1 -- Body/RConn1

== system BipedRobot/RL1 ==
  Body : mblibv1/Bodies/Body  LConnTagsString=CG|CS1  RConnTagsString=CS2  UpdateFromCAD=off  DialogClass=MechanicalBodyBlock  Mass=Mass.RL1  MassUnits=kg  InertiaUnits=kg*m^2  Inertia=Inertia.RL1  Shape=Cylinder  ShapeDims=[1 1]  ShapeUnits=m  ShapeUse=false  Density=1  DensityUnits=kg/m^3  DensityUse=false  GraphicsMode=MACHINE_DEFAULT  BodyColorSelMode=MACHINE_DEFAULT  BodyColor=[1;0;0]  AttachedToCS=CG  CG=Left$CG$[-6.4 -13.1 0]$CS1$CS1$mm$[0 0 0]$Euler X-Y-Z$deg$WORLD$true  WorkingFrames=Left$CS1$[0 -20 40]$WORLD$WORLD$mm$[0 0 0]$Euler X-Y-Z$deg$WORLD$true#Right$CS2$[0 0 0]$CS1$CS1$mm$[0 0 0]$Euler X-Y-Z$deg$WORLD$true  CGPos=[-6.4 -13.1 0]  CGRot=[0 0 0]  CS0Pos=[]  CS0Rot=[]  CS1Pos=[0 -20 40]  CS1Rot=[0 0 0]  CS2Pos=[0 0 0]  CS2Rot=[0 0 0]  CS3Pos=[]  CS3Rot=[]  CS4Pos=[]  CS4Rot=[]  CS5Pos=[]  CS5Rot=[]  CS6Pos=[]  CS6Rot=[]  CS7Pos=[]  CS7Rot=[]  CS8Pos=[]  CS8Rot=[]  CS9Pos=[]  CS9Rot=[]  CS10Pos=[]  CS10Rot=[]  CS11Pos=[]  CS11Rot=[]  CS12Pos=[]  CS12Rot=[]  CS13Pos=[]  CS13Rot=[]  CS14Pos=[]  CS14Rot=[]  CS15Pos=[]  CS15Rot=[]  CS16Pos=[]  CS16Rot=[]  CS17Pos=[]  CS17Rot=[]  CS18Pos=[]  CS18Rot=[]  CS19Pos=[]  CS19Rot=[]  CS20Pos=[]  CS20Rot=[]
  Body Sensor : mblibv1/Sensors &  Actuators/Body Sensor  UpdateFromCAD=off  PhysicalDomain=Mechanical  PortType=blob  Muxed=off  Pose=off  Angle=on  AngleUnits=deg  ArcVelocity=off  ArcVelocityUnits=deg/s  ArcAcceleration=off  ArcAccelerationUnits=deg/s^2  CoordPosition=on  CoordPositionUnits=m  Velocity=off  VelocityUnits=m/s  Acceleration=off  AccelerationUnits=m/s^2  Quaternion=on  QuaternionDT=off  QuaternionDDT=off  QuaternionUnits=off  OutputVector=[1]  ActiveIO=on  Width=3  DialogClass=MechanicalSensorBlock  ReferenceFrame=Absolute (World)
  From Workspace : FromWorkspace  VariableName=Motion.RL1  SampleTime=0
  Joint Actuator : mblibv1/Sensors &  Actuators/Joint Actuator  UpdateFromCAD=off  PhysicalDomain=Mechanical  PortType=blob  ActuationStyle=Motion  AngleUnits=deg  ArcVelocityUnits=deg/s  ArcAccelerationUnits=deg/s^2  CoordPositionUnits=m  VelocityUnits=m/s  AccelerationUnits=m/s^2  ForceUnits=N  TorqueUnits=N-m  ActiveIO=on  Width=3  DialogClass=MechanicalActuatorBlock  Primitive=R1  ReferenceFrame=Absolute (INERTIAL)
  Mechanical Branching Bar : mblibv1/Utilities/Mechanical Branching Bar  LConnTagsString=_newl0  RConnTagsString=SA0|SA1  UpdateFromCAD=off  DialogClass=MechanicalBranchingBarBlock  NumSAPorts=2
  Revolute : mblibv1/Joints/Revolute  LConnTagsString=__newl0|SA1  RConnTagsString=__newr0  UpdateFromCAD=off  NumSAPorts=1  CutJoint=off  MarkAsCut=off  Primitives=revolute  PrimitiveProps=R1$World$[0 -1 0]$revolute  DialogClass=JointBlock  R1Axis=[0 -1 0]
  C1 : PMIOPort  Port=1  Side=Right
  C2 : PMIOPort  Port=2  Side=Left
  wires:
  From Workspace/1 -> Joint Actuator/1
  Body Sensor/1 -> [CG_RL1]
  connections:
  Body/LConn2 -- C2/RConn1
  Revolute/LConn1 -- Body/RConn1
  Revolute/RConn1 -- C1/RConn1
  Joint Actuator/RConn1 -- Mechanical Branching Bar/RConn1
  Mechanical Branching Bar/LConn1 -- Revolute/LConn2
  Body/LConn1 -- Body Sensor/LConn1

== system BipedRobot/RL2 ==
  Body : mblibv1/Bodies/Body  LConnTagsString=CG|CS1  RConnTagsString=CS2  UpdateFromCAD=off  DialogClass=MechanicalBodyBlock  Mass=Mass.RL2  MassUnits=kg  InertiaUnits=kg*m^2  Inertia=Inertia.RL2  Shape=Cylinder  ShapeDims=[1 1]  ShapeUnits=m  ShapeUse=false  Density=1  DensityUnits=kg/m^3  DensityUse=false  GraphicsMode=MACHINE_DEFAULT  BodyColorSelMode=MACHINE_DEFAULT  BodyColor=[1;0;0]  AttachedToCS=CG  CG=Left$CG$[10.55 -32.59 38.17]$CS1$CS1$mm$[0 0 0]$Euler X-Y-Z$deg$WORLD$true  WorkingFrames=Left$CS1$[0 -20 40]$WORLD$WORLD$mm$[0 0 0]$Euler X-Y-Z$deg$WORLD$true#Right$CS2$[0 0 85]$CS1$CS1$mm$[0 0 0]$Euler X-Y-Z$deg$WORLD$true  CGPos=[10.55 -32.59 38.17]  CGRot=[0 0 0]  CS0Pos=[]  CS0Rot=[]  CS1Pos=[0 -20 40]  CS1Rot=[0 0 0]  CS2Pos=[0 0 85]  CS2Rot=[0 0 0]  CS3Pos=[]  CS3Rot=[]  CS4Pos=[]  CS4Rot=[]  CS5Pos=[]  CS5Rot=[]  CS6Pos=[]  CS6Rot=[]  CS7Pos=[]  CS7Rot=[]  CS8Pos=[]  CS8Rot=[]  CS9Pos=[]  CS9Rot=[]  CS10Pos=[]  CS10Rot=[]  CS11Pos=[]  CS11Rot=[]  CS12Pos=[]  CS12Rot=[]  CS13Pos=[]  CS13Rot=[]  CS14Pos=[]  CS14Rot=[]  CS15Pos=[]  CS15Rot=[]  CS16Pos=[]  CS16Rot=[]  CS17Pos=[]  CS17Rot=[]  CS18Pos=[]  CS18Rot=[]  CS19Pos=[]  CS19Rot=[]  CS20Pos=[]  CS20Rot=[]
  Body Sensor : mblibv1/Sensors &  Actuators/Body Sensor  UpdateFromCAD=off  PhysicalDomain=Mechanical  PortType=blob  Muxed=off  Pose=off  Angle=on  AngleUnits=deg  ArcVelocity=off  ArcVelocityUnits=deg/s  ArcAcceleration=off  ArcAccelerationUnits=deg/s^2  CoordPosition=on  CoordPositionUnits=m  Velocity=off  VelocityUnits=m/s  Acceleration=off  AccelerationUnits=m/s^2  Quaternion=on  QuaternionDT=off  QuaternionDDT=off  QuaternionUnits=off  OutputVector=[1]  ActiveIO=on  Width=3  DialogClass=MechanicalSensorBlock  ReferenceFrame=Absolute (World)
  From Workspace : FromWorkspace  VariableName=Motion.RL2  SampleTime=0
  Joint Actuator : mblibv1/Sensors &  Actuators/Joint Actuator  UpdateFromCAD=off  PhysicalDomain=Mechanical  PortType=blob  ActuationStyle=Motion  AngleUnits=deg  ArcVelocityUnits=deg/s  ArcAccelerationUnits=deg/s^2  CoordPositionUnits=m  VelocityUnits=m/s  AccelerationUnits=m/s^2  ForceUnits=N  TorqueUnits=N-m  ActiveIO=on  Width=3  DialogClass=MechanicalActuatorBlock  Primitive=R1  ReferenceFrame=Absolute (INERTIAL)
  Mechanical Branching Bar : mblibv1/Utilities/Mechanical Branching Bar  LConnTagsString=_newl0  RConnTagsString=SA0|SA1  UpdateFromCAD=off  DialogClass=MechanicalBranchingBarBlock  NumSAPorts=2
  Revolute : mblibv1/Joints/Revolute  LConnTagsString=__newl0|SA1  RConnTagsString=__newr0  UpdateFromCAD=off  NumSAPorts=1  CutJoint=off  MarkAsCut=off  Primitives=revolute  PrimitiveProps=R1$World$[0 -1 0]$revolute  DialogClass=JointBlock  R1Axis=[0 -1 0]
  C1 : PMIOPort  Port=1  Side=Right
  C2 : PMIOPort  Port=2  Side=Left
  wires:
  From Workspace/1 -> Joint Actuator/1
  Body Sensor/1 -> [CG_RL2]
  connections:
  Body/LConn2 -- C2/RConn1
  Body/RConn1 -- Revolute/LConn1
  Revolute/RConn1 -- C1/RConn1
  Joint Actuator/RConn1 -- Mechanical Branching Bar/RConn1
  Mechanical Branching Bar/LConn1 -- Revolute/LConn2
  Body Sensor/LConn1 -- Body/LConn1

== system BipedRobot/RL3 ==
  Body : mblibv1/Bodies/Body  LConnTagsString=CG|CS2  RConnTagsString=CS1  UpdateFromCAD=off  DialogClass=MechanicalBodyBlock  Mass=Mass.RL3  MassUnits=kg  InertiaUnits=kg*m^2  Inertia=Inertia.RL3  Shape=Cylinder  ShapeDims=[1 1]  ShapeUnits=m  ShapeUse=false  Density=1  DensityUnits=kg/m^3  DensityUse=false  GraphicsMode=MACHINE_DEFAULT  BodyColorSelMode=MACHINE_DEFAULT  BodyColor=[1;0;0]  AttachedToCS=CG  CG=Left$CG$[7.6 -30.24 -48.36]$CS1$CS1$mm$[0 0 0]$Euler X-Y-Z$deg$WORLD$true  WorkingFrames=Right$CS1$[0 -20 210]$WORLD$WORLD$mm$[0 0 0]$Euler X-Y-Z$deg$WORLD$true#Left$CS2$[0 0 -85]$CS1$CS1$mm$[0 0 0]$Euler X-Y-Z$deg$WORLD$true  CGPos=[7.6 -30.24 -48.36]  CGRot=[0 0 0]  CS0Pos=[]  CS0Rot=[]  CS1Pos=[0 -20 210]  CS1Rot=[0 0 0]  CS2Pos=[0 0 -85]  CS2Rot=[0 0 0]  CS3Pos=[]  CS3Rot=[]  CS4Pos=[]  CS4Rot=[]  CS5Pos=[]  CS5Rot=[]  CS6Pos=[]  CS6Rot=[]  CS7Pos=[]  CS7Rot=[]  CS8Pos=[]  CS8Rot=[]  CS9Pos=[]  CS9Rot=[]  CS10Pos=[]  CS10Rot=[]  CS11Pos=[]  CS11Rot=[]  CS12Pos=[]  CS12Rot=[]  CS13Pos=[]  CS13Rot=[]  CS14Pos=[]  CS14Rot=[]  CS15Pos=[]  CS15Rot=[]  CS16Pos=[]  CS16Rot=[]  CS17Pos=[]  CS17Rot=[]  CS18Pos=[]  CS18Rot=[]  CS19Pos=[]  CS19Rot=[]  CS20Pos=[]  CS20Rot=[]
  Body Sensor : mblibv1/Sensors &  Actuators/Body Sensor  UpdateFromCAD=off  PhysicalDomain=Mechanical  PortType=blob  Muxed=off  Pose=off  Angle=on  AngleUnits=deg  ArcVelocity=off  ArcVelocityUnits=deg/s  ArcAcceleration=off  ArcAccelerationUnits=deg/s^2  CoordPosition=on  CoordPositionUnits=m  Velocity=off  VelocityUnits=m/s  Acceleration=off  AccelerationUnits=m/s^2  Quaternion=on  QuaternionDT=off  QuaternionDDT=off  QuaternionUnits=off  OutputVector=[1]  ActiveIO=on  Width=3  DialogClass=MechanicalSensorBlock  ReferenceFrame=Absolute (World)
  From Workspace : FromWorkspace  VariableName=Motion.RL3  SampleTime=0
  Joint Actuator : mblibv1/Sensors &  Actuators/Joint Actuator  UpdateFromCAD=off  PhysicalDomain=Mechanical  PortType=blob  ActuationStyle=Motion  AngleUnits=deg  ArcVelocityUnits=deg/s  ArcAccelerationUnits=deg/s^2  CoordPositionUnits=m  VelocityUnits=m/s  AccelerationUnits=m/s^2  ForceUnits=N  TorqueUnits=N-m  ActiveIO=on  Width=3  DialogClass=MechanicalActuatorBlock  Primitive=R1  ReferenceFrame=Absolute (INERTIAL)
  Mechanical Branching Bar : mblibv1/Utilities/Mechanical Branching Bar  LConnTagsString=_newl0  RConnTagsString=SA0|SA1  UpdateFromCAD=off  DialogClass=MechanicalBranchingBarBlock  NumSAPorts=2
  Revolute : mblibv1/Joints/Revolute  LConnTagsString=__newl0|SA1  RConnTagsString=__newr0  UpdateFromCAD=off  NumSAPorts=1  CutJoint=off  MarkAsCut=off  Primitives=revolute  PrimitiveProps=R1$World$[0 -1 0]$revolute  DialogClass=JointBlock  R1Axis=[0 -1 0]
  C1 : PMIOPort  Port=1  Side=Right
  C2 : PMIOPort  Port=2  Side=Left
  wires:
  From Workspace/1 -> Joint Actuator/1
  Body Sensor/1 -> [CG_RL3]
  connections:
  Body/LConn2 -- C2/RConn1
  Body/RConn1 -- Revolute/LConn1
  Revolute/RConn1 -- C1/RConn1
  Joint Actuator/RConn1 -- Mechanical Branching Bar/RConn1
  Mechanical Branching Bar/LConn1 -- Revolute/LConn2
  Body Sensor/LConn1 -- Body/LConn1

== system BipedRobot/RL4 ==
  Body : mblibv1/Bodies/Body  LConnTagsString=CS1  RConnTagsString=CG|CS2  UpdateFromCAD=off  DialogClass=MechanicalBodyBlock  Mass=Mass.RL4  MassUnits=kg  InertiaUnits=kg*m^2  Inertia=Inertia.RL4  Shape=Cylinder  ShapeDims=[1 1]  ShapeUnits=m  ShapeUse=false  Density=1  DensityUnits=kg/m^3  DensityUse=false  GraphicsMode=MACHINE_DEFAULT  BodyColorSelMode=MACHINE_DEFAULT  BodyColor=[1;0;0]  AttachedToCS=CG  CG=Right$CG$[22.94 -16.61 0]$CS1$CS1$mm$[0 0 0]$Euler X-Y-Z$deg$WORLD$true  WorkingFrames=Left$CS1$[0 -20 210]$WORLD$WORLD$mm$[0 0 0]$Euler X-Y-Z$deg$WORLD$true#Right$CS2$[0 0 0]$CS1$CS1$mm$[0 0 0]$Euler X-Y-Z$deg$WORLD$true  CGPos=[22.94 -16.61 0]  CGRot=[0 0 0]  CS0Pos=[]  CS0Rot=[]  CS1Pos=[0 -20 210]  CS1Rot=[0 0 0]  CS2Pos=[0 0 0]  CS2Rot=[0 0 0]  CS3Pos=[]  CS3Rot=[]  CS4Pos=[]  CS4Rot=[]  CS5Pos=[]  CS5Rot=[]  CS6Pos=[]  CS6Rot=[]  CS7Pos=[]  CS7Rot=[]  CS8Pos=[]  CS8Rot=[]  CS9Pos=[]  CS9Rot=[]  CS10Pos=[]  CS10Rot=[]  CS11Pos=[]  CS11Rot=[]  CS12Pos=[]  CS12Rot=[]  CS13Pos=[]  CS13Rot=[]  CS14Pos=[]  CS14Rot=[]  CS15Pos=[]  CS15Rot=[]  CS16Pos=[]  CS16Rot=[]  CS17Pos=[]  CS17Rot=[]  CS18Pos=[]  CS18Rot=[]  CS19Pos=[]  CS19Rot=[]  CS20Pos=[]  CS20Rot=[]
  Body Sensor : mblibv1/Sensors &  Actuators/Body Sensor  UpdateFromCAD=off  PhysicalDomain=Mechanical  PortType=blob  Muxed=off  Pose=off  Angle=on  AngleUnits=deg  ArcVelocity=off  ArcVelocityUnits=deg/s  ArcAcceleration=off  ArcAccelerationUnits=deg/s^2  CoordPosition=on  CoordPositionUnits=m  Velocity=off  VelocityUnits=m/s  Acceleration=off  AccelerationUnits=m/s^2  Quaternion=on  QuaternionDT=off  QuaternionDDT=off  QuaternionUnits=off  OutputVector=[1]  ActiveIO=on  Width=3  DialogClass=MechanicalSensorBlock  ReferenceFrame=Absolute (World)
  From Workspace : FromWorkspace  VariableName=Motion.RL4  SampleTime=0
  Joint Actuator : mblibv1/Sensors &  Actuators/Joint Actuator  UpdateFromCAD=off  PhysicalDomain=Mechanical  PortType=blob  ActuationStyle=Motion  AngleUnits=deg  ArcVelocityUnits=deg/s  ArcAccelerationUnits=deg/s^2  CoordPositionUnits=m  VelocityUnits=m/s  AccelerationUnits=m/s^2  ForceUnits=N  TorqueUnits=N-m  ActiveIO=on  Width=3  DialogClass=MechanicalActuatorBlock  Primitive=R1  ReferenceFrame=Absolute (INERTIAL)
  Mechanical Branching Bar : mblibv1/Utilities/Mechanical Branching Bar  LConnTagsString=_newl0  RConnTagsString=SA0|SA1  UpdateFromCAD=off  DialogClass=MechanicalBranchingBarBlock  NumSAPorts=2
  Revolute : mblibv1/Joints/Revolute  LConnTagsString=__newl0|SA1  RConnTagsString=__newr0  UpdateFromCAD=off  NumSAPorts=1  CutJoint=off  MarkAsCut=off  Primitives=revolute  PrimitiveProps=R1$World$[-1 0 0]$revolute  DialogClass=JointBlock  R1Axis=[-1 0 0]
  C2 : PMIOPort  Port=1  Side=Left
  C1 : PMIOPort  Port=2  Side=Right
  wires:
  From Workspace/1 -> Joint Actuator/1
  Body Sensor/1 -> [CG_RL4]
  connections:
  C2/RConn1 -- Body/RConn2
  Revolute/LConn1 -- Body/LConn1
  Revolute/RConn1 -- C1/RConn1
  Mechanical Branching Bar/RConn1 -- Joint Actuator/RConn1
  Mechanical Branching Bar/LConn1 -- Revolute/LConn2
  Body/RConn1 -- Body Sensor/LConn1

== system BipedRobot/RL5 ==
  Body : mblibv1/Bodies/Body  LConnTagsString=CG|CS1  RConnTagsString=CS2  UpdateFromCAD=off  DialogClass=MechanicalBodyBlock  Mass=Mass.RL5  MassUnits=kg  InertiaUnits=kg*m^2  Inertia=Inertia.RL5  Shape=Cylinder  ShapeDims=[1 1]  ShapeUnits=m  ShapeUse=false  Density=1  DensityUnits=kg/m^3  DensityUse=false  GraphicsMode=MACHINE_DEFAULT  BodyColorSelMode=MACHINE_DEFAULT  BodyColor=[1;0;0]  AttachedToCS=CG  CG=Left$CG$[7.11 0 5.09]$CS1$CS1$mm$[0 0 0]$Euler X-Y-Z$deg$WORLD$true  WorkingFrames=Left$CS1$[0 -20 210]$WORLD$WORLD$mm$[0 0 0]$Euler X-Y-Z$deg$WORLD$true#Right$CS2$[0 0 0]$CS1$CS1$mm$[0 0 0]$Euler X-Y-Z$deg$WORLD$true  CGPos=[7.11 0 5.09]  CGRot=[0 0 0]  CS0Pos=[]  CS0Rot=[]  CS1Pos=[0 -20 210]  CS1Rot=[0 0 0]  CS2Pos=[0 0 0]  CS2Rot=[0 0 0]  CS3Pos=[]  CS3Rot=[]  CS4Pos=[]  CS4Rot=[]  CS5Pos=[]  CS5Rot=[]  CS6Pos=[]  CS6Rot=[]  CS7Pos=[]  CS7Rot=[]  CS8Pos=[]  CS8Rot=[]  CS9Pos=[]  CS9Rot=[]  CS10Pos=[]  CS10Rot=[]  CS11Pos=[]  CS11Rot=[]  CS12Pos=[]  CS12Rot=[]  CS13Pos=[]  CS13Rot=[]  CS14Pos=[]  CS14Rot=[]  CS15Pos=[]  CS15Rot=[]  CS16Pos=[]  CS16Rot=[]  CS17Pos=[]  CS17Rot=[]  CS18Pos=[]  CS18Rot=[]  CS19Pos=[]  CS19Rot=[]  CS20Pos=[]  CS20Rot=[]
  Body Sensor : mblibv1/Sensors &  Actuators/Body Sensor  UpdateFromCAD=off  PhysicalDomain=Mechanical  PortType=blob  Muxed=off  Pose=off  Angle=on  AngleUnits=deg  ArcVelocity=off  ArcVelocityUnits=deg/s  ArcAcceleration=off  ArcAccelerationUnits=deg/s^2  CoordPosition=on  CoordPositionUnits=m  Velocity=off  VelocityUnits=m/s  Acceleration=off  AccelerationUnits=m/s^2  Quaternion=on  QuaternionDT=off  QuaternionDDT=off  QuaternionUnits=off  OutputVector=[1]  ActiveIO=on  Width=3  DialogClass=MechanicalSensorBlock  ReferenceFrame=Absolute (World)
  From Workspace : FromWorkspace  VariableName=Motion.RL5  SampleTime=0
  Joint Actuator : mblibv1/Sensors &  Actuators/Joint Actuator  UpdateFromCAD=off  PhysicalDomain=Mechanical  PortType=blob  ActuationStyle=Motion  AngleUnits=deg  ArcVelocityUnits=deg/s  ArcAccelerationUnits=deg/s^2  CoordPositionUnits=m  VelocityUnits=m/s  AccelerationUnits=m/s^2  ForceUnits=N  TorqueUnits=N-m  ActiveIO=on  Width=3  DialogClass=MechanicalActuatorBlock  Primitive=R1  ReferenceFrame=Absolute (INERTIAL)
  Mechanical Branching Bar : mblibv1/Utilities/Mechanical Branching Bar  LConnTagsString=_newl0  RConnTagsString=SA0|SA1  UpdateFromCAD=off  DialogClass=MechanicalBranchingBarBlock  NumSAPorts=2
  Revolute : mblibv1/Joints/Revolute  LConnTagsString=__newl0|SA1  RConnTagsString=__newr0  UpdateFromCAD=off  NumSAPorts=1  CutJoint=off  MarkAsCut=off  Primitives=revolute  PrimitiveProps=R1$World$[0 0 -1]$revolute  DialogClass=JointBlock  R1Axis=[0 0 -1]
  C1 : PMIOPort  Port=1  Side=Right
  C2 : PMIOPort  Port=2  Side=Left
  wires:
  From Workspace/1 -> Joint Actuator/1
  Body Sensor/1 -> [CG_RL5]
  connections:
  C2/RConn1 -- Body/LConn2
  Revolute/LConn1 -- Body/RConn1
  Revolute/RConn1 -- C1/RConn1
  Mechanical Branching Bar/RConn1 -- Joint Actuator/RConn1
  Mechanical Branching Bar/LConn1 -- Revolute/LConn2
  Body Sensor/LConn1 -- Body/LConn1

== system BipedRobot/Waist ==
  Body : mblibv1/Bodies/Body  LConnTagsString=CS2  RConnTagsString=CG|CS3  UpdateFromCAD=off  DialogClass=MechanicalBodyBlock  Mass=Mass.WAIST  MassUnits=kg  InertiaUnits=kg*m^2  Inertia=Inertia.WAIST  Shape=Cylinder  ShapeDims=[1 1]  ShapeUnits=m  ShapeUse=false  Density=1  DensityUnits=kg/m^3  DensityUse=false  GraphicsMode=MACHINE_DEFAULT  BodyColorSelMode=MACHINE_DEFAULT  BodyColor=[1;0;0]  AttachedToCS=CG  CG=Right$CG$[0 0 31.68]$CS1$CS1$mm$[0 0 0]$Euler X-Y-Z$deg$WORLD$true  WorkingFrames=Left$CS1$[0 0 244]$WORLD$WORLD$mm$[0 0 0]$Euler X-Y-Z$deg$WORLD$false#Left$CS2$[0 -20 -34]$CS1$CS1$mm$[0 0 0]$Euler X-Y-Z$deg$WORLD$true#Right$CS3$[0 20 -34]$CS1$CS1$mm$[0 0 0]$Euler X-Y-Z$deg$WORLD$true  CGPos=[0 0 31.68]  CGRot=[0 0 0]  CS0Pos=[]  CS0Rot=[]  CS1Pos=[0 0 244]  CS1Rot=[0 0 0]  CS2Pos=[0 -20 -34]  CS2Rot=[0 0 0]  CS3Pos=[0 20 -34]  CS3Rot=[0 0 0]  CS4Pos=[]  CS4Rot=[]  CS5Pos=[]  CS5Rot=[]  CS6Pos=[]  CS6Rot=[]  CS7Pos=[]  CS7Rot=[]  CS8Pos=[]  CS8Rot=[]  CS9Pos=[]  CS9Rot=[]  CS10Pos=[]  CS10Rot=[]  CS11Pos=[]  CS11Rot=[]  CS12Pos=[]  CS12Rot=[]  CS13Pos=[]  CS13Rot=[]  CS14Pos=[]  CS14Rot=[]  CS15Pos=[]  CS15Rot=[]  CS16Pos=[]  CS16Rot=[]  CS17Pos=[]  CS17Rot=[]  CS18Pos=[]  CS18Rot=[]  CS19Pos=[]  CS19Rot=[]  CS20Pos=[]  CS20Rot=[]
  Body Sensor : mblibv1/Sensors &  Actuators/Body Sensor  UpdateFromCAD=off  PhysicalDomain=Mechanical  PortType=blob  Muxed=off  Pose=off  Angle=on  AngleUnits=deg  ArcVelocity=off  ArcVelocityUnits=deg/s  ArcAcceleration=off  ArcAccelerationUnits=deg/s^2  CoordPosition=on  CoordPositionUnits=m  Velocity=off  VelocityUnits=m/s  Acceleration=off  AccelerationUnits=m/s^2  Quaternion=on  QuaternionDT=off  QuaternionDDT=off  QuaternionUnits=off  OutputVector=[1]  ActiveIO=on  Width=3  DialogClass=MechanicalSensorBlock  ReferenceFrame=Absolute (World)
  C2 : PMIOPort  Port=1  Side=Left
  C1 : PMIOPort  Port=2  Side=Left
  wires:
  Body Sensor/1 -> [CG_WAIST]
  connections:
  Body/LConn1 -- C2/RConn1
  Body/RConn2 -- C1/RConn1
  Body/RConn1 -- Body Sensor/LConn1

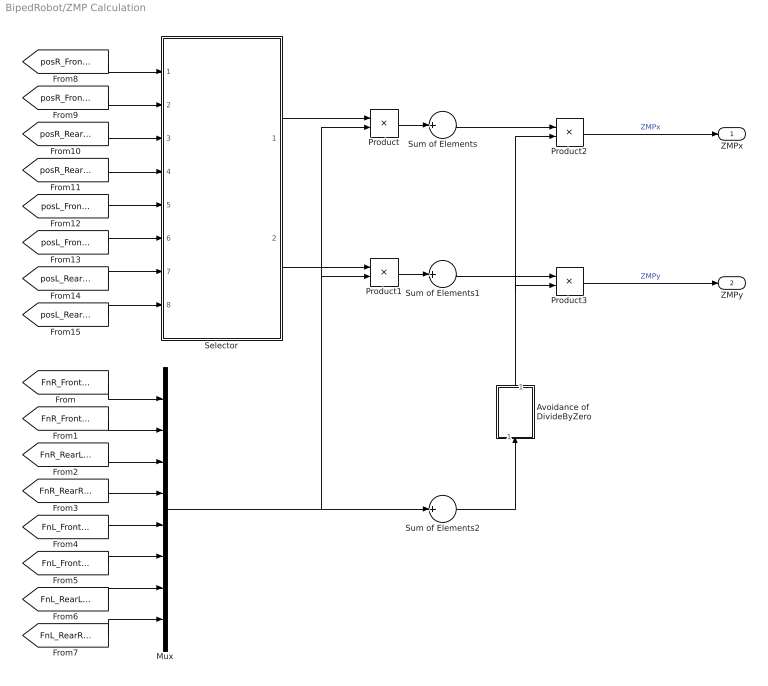
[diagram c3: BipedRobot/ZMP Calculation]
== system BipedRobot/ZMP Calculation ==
  Avoidance of DivideByZero : Subsystem
  Mux : Mux  Inputs=8
  Product : Product
  Product1 : Product
  Product2 : Product  Inputs=*/
  Product3 : Product  Inputs=*/
  Selector : Subsystem
  Sum of Elements : Sum  Inputs=+
  Sum of Elements1 : Sum  Inputs=+
  Sum of Elements2 : Sum  Inputs=+
  ZMPx : Outport
  ZMPy : Outport  Port=2
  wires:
  [FnR_FrontLeft] -> Mux/1
  [FnR_FrontRight] -> Mux/2
  [FnR_RearLeft] -> Mux/3
  [FnR_RearRight] -> Mux/4
  [FnL_FrontLeft] -> Mux/5
  [FnL_FrontRight] -> Mux/6
  [FnL_RearLeft] -> Mux/7
  [FnL_RearRight] -> Mux/8
  Selector/1(xvec) -> Product/1
  Mux/1 -> Product/2, Product1/2, Sum of Elements2/1
  Selector/2(yvec) -> Product1/1
  Product/1 -> Sum of Elements/1
  Product1/1 -> Sum of Elements1/1
  Sum of Elements/1 -> Product2/1
  Sum of Elements2/1 -> Avoidance of DivideByZero/1(u)
  Sum of Elements1/1 -> Product3/1
  Product2/1 -> ZMPx/1  "ZMPx"
  Product3/1 -> ZMPy/1  "ZMPy"
  Avoidance of DivideByZero/1(y) -> Product2/2, Product3/2
  [posR_FrontLeft] -> Selector/1(posR_FrontLeft)
  [posR_FrontRight] -> Selector/2(posR_FrontRight)
  [posR_RearLeft] -> Selector/3(posR_RearLeft)
  [posR_RearRight] -> Selector/4(posR_RearRight)
  [posL_FrontLeft] -> Selector/5(posL_FrontLeft)
  [posL_FrontRight] -> Selector/6(posL_FrontRight)
  [posL_RearLeft] -> Selector/7(posL_RearLeft)
  [posL_RearRight] -> Selector/8(posL_RearRight)

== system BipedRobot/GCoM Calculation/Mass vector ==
  Constant : Constant  Value=Mass.RL0
  Constant1 : Constant  Value=Mass.RL1
  Constant10 : Constant  Value=Mass.LL4
  Constant11 : Constant  Value=Mass.LL5
  Constant12 : Constant  Value=Mass.WAIST
  Constant2 : Constant  Value=Mass.RL2
  Constant3 : Constant  Value=Mass.RL3
  Constant4 : Constant  Value=Mass.RL4
  Constant5 : Constant  Value=Mass.RL5
  Constant6 : Constant  Value=Mass.LL0
  Constant7 : Constant  Value=Mass.LL1
  Constant8 : Constant  Value=Mass.LL2
  Constant9 : Constant  Value=Mass.LL3
  Mux : Mux  Inputs=13
  Mvec : Outport
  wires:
  Constant7/1 -> Mux/8
  Constant6/1 -> Mux/7
  Constant5/1 -> Mux/6
  Constant4/1 -> Mux/5
  Constant3/1 -> Mux/4
  Constant2/1 -> Mux/3
  Constant1/1 -> Mux/2
  Constant/1 -> Mux/1
  Constant8/1 -> Mux/9
  Constant9/1 -> Mux/10
  Constant10/1 -> Mux/11
  Constant11/1 -> Mux/12
  Constant12/1 -> Mux/13
  Mux/1 -> Mvec/1

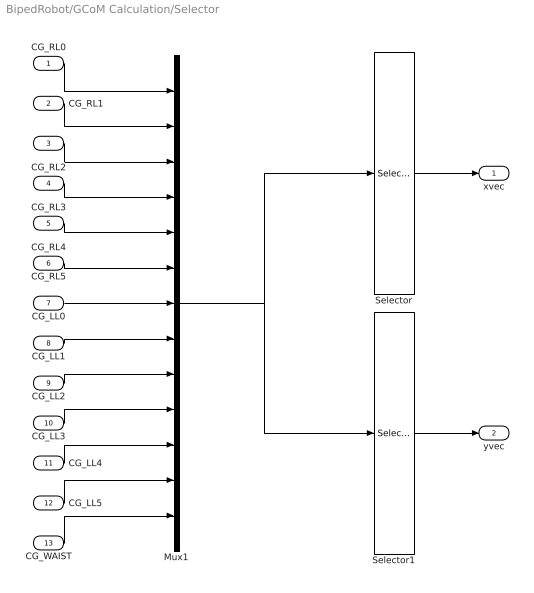
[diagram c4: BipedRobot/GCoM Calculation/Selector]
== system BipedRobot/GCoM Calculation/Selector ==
  CG_RL0 : Inport
  CG_RL1 : Inport  Port=2
  CG_RL2 : Inport  Port=3
  CG_RL3 : Inport  Port=4
  CG_RL4 : Inport  Port=5
  CG_RL5 : Inport  Port=6
  CG_LL0 : Inport  Port=7
  CG_LL1 : Inport  Port=8
  CG_LL2 : Inport  Port=9
  CG_LL3 : Inport  Port=10
  CG_LL4 : Inport  Port=11
  CG_LL5 : Inport  Port=12
  CG_WAIST : Inport  Port=13
  Mux1 : Mux  Inputs=13
  Selector : Selector  InputPortWidth=39  IndexOptions=Index vector (dialog)  Indices=1:3:39  OutputSizes=1
  Selector1 : Selector  InputPortWidth=39  IndexOptions=Index vector (dialog)  Indices=2:3:39  OutputSizes=1
  xvec : Outport
  yvec : Outport  Port=2
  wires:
  CG_RL0/1 -> Mux1/1
  CG_RL1/1 -> Mux1/2
  CG_RL2/1 -> Mux1/3
  CG_RL3/1 -> Mux1/4
  CG_RL4/1 -> Mux1/5
  CG_RL5/1 -> Mux1/6
  CG_LL0/1 -> Mux1/7
  CG_LL1/1 -> Mux1/8
  CG_LL2/1 -> Mux1/9
  CG_LL3/1 -> Mux1/10
  CG_LL4/1 -> Mux1/11
  CG_LL5/1 -> Mux1/12
  CG_WAIST/1 -> Mux1/13
  Mux1/1 -> Selector/1, Selector1/1
  Selector/1 -> xvec/1
  Selector1/1 -> yvec/1
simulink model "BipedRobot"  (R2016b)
settings: Solver=ode15s  StartTime=0.0  StopTime=Tend  FixedStep=0.001  RelTol=1e-3  AbsTol=1e-4  EnableMultiTasking=on
PreLoadFcn:
  | BipedRobot_param
  | load walk_forward
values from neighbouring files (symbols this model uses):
  bn = 50    [BipedRobot_param.m]    (also in SimpleContact_param.m)
  bt = 50    [BipedRobot_param.m]    (also in SimpleContact_param.m)
  kn = 5000    [BipedRobot_param.m]    (also in SimpleContact_param.m)
  kt = 5000    [BipedRobot_param.m]    (also in SimpleContact_param.m)
  mu_d = 0.8    [BipedRobot_param.m]    (also in SimpleContact_param.m)
  mu_s = 2    [BipedRobot_param.m]    (also in SimpleContact_param.m)
  N = 100    [initialize_para.m]    (also in main.m = walk_para.N; walk_parameter.m = 5)
  s = robot_para.s    [kinematics_calc.m]    (also in plot_graph.m; robot_parameter.m = 40; robot_view.m)
  zvt = 1e-3    (= 0.001)    [BipedRobot_param.m]    (also in SimpleContact_param.m)
undefined symbols (not defined in the file or in its folder): deg, Inertia, kg, m, Mass
libraries: mblibv1 x89, simulink x1
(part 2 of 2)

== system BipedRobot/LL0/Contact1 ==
  Body Actuator : mblibv1/Sensors &  Actuators/Body Actuator  UpdateFromCAD=off  PhysicalDomain=Mechanical  PortType=blob  ActuationStyle=Force  AngleUnits=deg  ArcVelocityUnits=deg/s  ArcAccelerationUnits=deg/s^2  CoordPositionUnits=m  VelocityUnits=m/s  AccelerationUnits=m/s^2  ForceUnits=N  TorqueUnits=N-m  ActiveIO=on  Width=3  DialogClass=MechanicalActuatorBlock  ReferenceFrame=Absolute (World)  Angle=off  CoordPosition=on  Force=on  Torque=off
  Body Sensor : mblibv1/Sensors &  Actuators/Body Sensor  UpdateFromCAD=off  PhysicalDomain=Mechanical  PortType=blob  Muxed=off  Pose=off  Angle=on  AngleUnits=deg  ArcVelocity=off  ArcVelocityUnits=deg/s  ArcAcceleration=off  ArcAccelerationUnits=deg/s^2  CoordPosition=on  CoordPositionUnits=m  Velocity=on  VelocityUnits=m/s  Acceleration=off  AccelerationUnits=m/s^2  Quaternion=on  QuaternionDT=off  QuaternionDDT=off  QuaternionUnits=off  OutputVector=[ 3 3 ]  ActiveIO=on  Width=6  DialogClass=MechanicalSensorBlock  ReferenceFrame=Absolute (World)
  Contact Force : Subsystem
  Mechanical Branching Bar : mblibv1/Utilities/Mechanical Branching Bar  LConnTagsString=_newl0  RConnTagsString=SA0|SA1  UpdateFromCAD=off  DialogClass=MechanicalBranchingBarBlock  NumSAPorts=2
  CS : PMIOPort  Port=1  Side=Right
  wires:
  Body Sensor/1 -> [posL_FrontRight], Contact Force/1(pos)
  Body Sensor/2 -> Contact Force/2(vel)
  Contact Force/1(force) -> Body Actuator/1
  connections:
  Mechanical Branching Bar/RConn1 -- Body Sensor/LConn1
  Mechanical Branching Bar/RConn2 -- Body Actuator/RConn1
  CS/RConn1 -- Mechanical Branching Bar/LConn1

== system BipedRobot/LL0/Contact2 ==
  Body Actuator : mblibv1/Sensors &  Actuators/Body Actuator  UpdateFromCAD=off  PhysicalDomain=Mechanical  PortType=blob  ActuationStyle=Force  AngleUnits=deg  ArcVelocityUnits=deg/s  ArcAccelerationUnits=deg/s^2  CoordPositionUnits=m  VelocityUnits=m/s  AccelerationUnits=m/s^2  ForceUnits=N  TorqueUnits=N-m  ActiveIO=on  Width=3  DialogClass=MechanicalActuatorBlock  ReferenceFrame=Absolute (World)  Angle=off  CoordPosition=on  Force=on  Torque=off
  Body Sensor : mblibv1/Sensors &  Actuators/Body Sensor  UpdateFromCAD=off  PhysicalDomain=Mechanical  PortType=blob  Muxed=off  Pose=off  Angle=on  AngleUnits=deg  ArcVelocity=off  ArcVelocityUnits=deg/s  ArcAcceleration=off  ArcAccelerationUnits=deg/s^2  CoordPosition=on  CoordPositionUnits=m  Velocity=on  VelocityUnits=m/s  Acceleration=off  AccelerationUnits=m/s^2  Quaternion=on  QuaternionDT=off  QuaternionDDT=off  QuaternionUnits=off  OutputVector=[ 3 3 ]  ActiveIO=on  Width=6  DialogClass=MechanicalSensorBlock  ReferenceFrame=Absolute (World)
  Contact Force : Subsystem
  Mechanical Branching Bar : mblibv1/Utilities/Mechanical Branching Bar  LConnTagsString=_newl0  RConnTagsString=SA0|SA1  UpdateFromCAD=off  DialogClass=MechanicalBranchingBarBlock  NumSAPorts=2
  CS : PMIOPort  Port=1  Side=Right
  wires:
  Contact Force/1(force) -> Body Actuator/1
  Body Sensor/2 -> Contact Force/2(vel)
  Body Sensor/1 -> [posL_RearRight], Contact Force/1(pos)
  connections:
  CS/RConn1 -- Mechanical Branching Bar/LConn1
  Mechanical Branching Bar/RConn2 -- Body Actuator/RConn1
  Mechanical Branching Bar/RConn1 -- Body Sensor/LConn1

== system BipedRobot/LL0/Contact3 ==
  Body Actuator : mblibv1/Sensors &  Actuators/Body Actuator  UpdateFromCAD=off  PhysicalDomain=Mechanical  PortType=blob  ActuationStyle=Force  AngleUnits=deg  ArcVelocityUnits=deg/s  ArcAccelerationUnits=deg/s^2  CoordPositionUnits=m  VelocityUnits=m/s  AccelerationUnits=m/s^2  ForceUnits=N  TorqueUnits=N-m  ActiveIO=on  Width=3  DialogClass=MechanicalActuatorBlock  ReferenceFrame=Absolute (World)  Angle=off  CoordPosition=on  Force=on  Torque=off
  Body Sensor : mblibv1/Sensors &  Actuators/Body Sensor  UpdateFromCAD=off  PhysicalDomain=Mechanical  PortType=blob  Muxed=off  Pose=off  Angle=on  AngleUnits=deg  ArcVelocity=off  ArcVelocityUnits=deg/s  ArcAcceleration=off  ArcAccelerationUnits=deg/s^2  CoordPosition=on  CoordPositionUnits=m  Velocity=on  VelocityUnits=m/s  Acceleration=off  AccelerationUnits=m/s^2  Quaternion=on  QuaternionDT=off  QuaternionDDT=off  QuaternionUnits=off  OutputVector=[ 3 3 ]  ActiveIO=on  Width=6  DialogClass=MechanicalSensorBlock  ReferenceFrame=Absolute (World)
  Contact Force : Subsystem
  Mechanical Branching Bar : mblibv1/Utilities/Mechanical Branching Bar  LConnTagsString=_newl0  RConnTagsString=SA0|SA1  UpdateFromCAD=off  DialogClass=MechanicalBranchingBarBlock  NumSAPorts=2
  CS : PMIOPort  Port=1  Side=Right
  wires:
  Contact Force/1(force) -> Body Actuator/1
  Body Sensor/2 -> Contact Force/2(vel)
  Body Sensor/1 -> [posL_FrontLeft], Contact Force/1(pos)
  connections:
  CS/RConn1 -- Mechanical Branching Bar/LConn1
  Mechanical Branching Bar/RConn2 -- Body Actuator/RConn1
  Mechanical Branching Bar/RConn1 -- Body Sensor/LConn1

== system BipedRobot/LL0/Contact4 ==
  Body Actuator : mblibv1/Sensors &  Actuators/Body Actuator  UpdateFromCAD=off  PhysicalDomain=Mechanical  PortType=blob  ActuationStyle=Force  AngleUnits=deg  ArcVelocityUnits=deg/s  ArcAccelerationUnits=deg/s^2  CoordPositionUnits=m  VelocityUnits=m/s  AccelerationUnits=m/s^2  ForceUnits=N  TorqueUnits=N-m  ActiveIO=on  Width=3  DialogClass=MechanicalActuatorBlock  ReferenceFrame=Absolute (World)  Angle=off  CoordPosition=on  Force=on  Torque=off
  Body Sensor : mblibv1/Sensors &  Actuators/Body Sensor  UpdateFromCAD=off  PhysicalDomain=Mechanical  PortType=blob  Muxed=off  Pose=off  Angle=on  AngleUnits=deg  ArcVelocity=off  ArcVelocityUnits=deg/s  ArcAcceleration=off  ArcAccelerationUnits=deg/s^2  CoordPosition=on  CoordPositionUnits=m  Velocity=on  VelocityUnits=m/s  Acceleration=off  AccelerationUnits=m/s^2  Quaternion=on  QuaternionDT=off  QuaternionDDT=off  QuaternionUnits=off  OutputVector=[ 3 3 ]  ActiveIO=on  Width=6  DialogClass=MechanicalSensorBlock  ReferenceFrame=Absolute (World)
  Contact Force : Subsystem
  Mechanical Branching Bar : mblibv1/Utilities/Mechanical Branching Bar  LConnTagsString=_newl0  RConnTagsString=SA0|SA1  UpdateFromCAD=off  DialogClass=MechanicalBranchingBarBlock  NumSAPorts=2
  CS : PMIOPort  Port=1  Side=Right
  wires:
  Body Sensor/1 -> [posL_RearLeft], Contact Force/1(pos)
  Body Sensor/2 -> Contact Force/2(vel)
  Contact Force/1(force) -> Body Actuator/1
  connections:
  Mechanical Branching Bar/RConn1 -- Body Sensor/LConn1
  Mechanical Branching Bar/RConn2 -- Body Actuator/RConn1
  CS/RConn1 -- Mechanical Branching Bar/LConn1

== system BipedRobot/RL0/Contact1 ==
  Body Actuator : mblibv1/Sensors &  Actuators/Body Actuator  UpdateFromCAD=off  PhysicalDomain=Mechanical  PortType=blob  ActuationStyle=Force  AngleUnits=deg  ArcVelocityUnits=deg/s  ArcAccelerationUnits=deg/s^2  CoordPositionUnits=m  VelocityUnits=m/s  AccelerationUnits=m/s^2  ForceUnits=N  TorqueUnits=N-m  ActiveIO=on  Width=3  DialogClass=MechanicalActuatorBlock  ReferenceFrame=Absolute (World)  Angle=off  CoordPosition=on  Force=on  Torque=off
  Body Sensor : mblibv1/Sensors &  Actuators/Body Sensor  UpdateFromCAD=off  PhysicalDomain=Mechanical  PortType=blob  Muxed=off  Pose=off  Angle=on  AngleUnits=deg  ArcVelocity=off  ArcVelocityUnits=deg/s  ArcAcceleration=off  ArcAccelerationUnits=deg/s^2  CoordPosition=on  CoordPositionUnits=m  Velocity=on  VelocityUnits=m/s  Acceleration=off  AccelerationUnits=m/s^2  Quaternion=on  QuaternionDT=off  QuaternionDDT=off  QuaternionUnits=off  OutputVector=[ 3 3 ]  ActiveIO=on  Width=6  DialogClass=MechanicalSensorBlock  ReferenceFrame=Absolute (World)
  Contact Force : Subsystem
  Mechanical Branching Bar : mblibv1/Utilities/Mechanical Branching Bar  LConnTagsString=_newl0  RConnTagsString=SA0|SA1  UpdateFromCAD=off  DialogClass=MechanicalBranchingBarBlock  NumSAPorts=2
  CS : PMIOPort  Port=1  Side=Right
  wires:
  Contact Force/1(force) -> Body Actuator/1
  Body Sensor/2 -> Contact Force/2(vel)
  Body Sensor/1 -> [posR_FrontLeft], Contact Force/1(pos)
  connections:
  CS/RConn1 -- Mechanical Branching Bar/LConn1
  Mechanical Branching Bar/RConn2 -- Body Actuator/RConn1
  Mechanical Branching Bar/RConn1 -- Body Sensor/LConn1

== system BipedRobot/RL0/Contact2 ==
  Body Actuator : mblibv1/Sensors &  Actuators/Body Actuator  UpdateFromCAD=off  PhysicalDomain=Mechanical  PortType=blob  ActuationStyle=Force  AngleUnits=deg  ArcVelocityUnits=deg/s  ArcAccelerationUnits=deg/s^2  CoordPositionUnits=m  VelocityUnits=m/s  AccelerationUnits=m/s^2  ForceUnits=N  TorqueUnits=N-m  ActiveIO=on  Width=3  DialogClass=MechanicalActuatorBlock  ReferenceFrame=Absolute (World)  Angle=off  CoordPosition=on  Force=on  Torque=off
  Body Sensor : mblibv1/Sensors &  Actuators/Body Sensor  UpdateFromCAD=off  PhysicalDomain=Mechanical  PortType=blob  Muxed=off  Pose=off  Angle=on  AngleUnits=deg  ArcVelocity=off  ArcVelocityUnits=deg/s  ArcAcceleration=off  ArcAccelerationUnits=deg/s^2  CoordPosition=on  CoordPositionUnits=m  Velocity=on  VelocityUnits=m/s  Acceleration=off  AccelerationUnits=m/s^2  Quaternion=on  QuaternionDT=off  QuaternionDDT=off  QuaternionUnits=off  OutputVector=[ 3 3 ]  ActiveIO=on  Width=6  DialogClass=MechanicalSensorBlock  ReferenceFrame=Absolute (World)
  Contact Force : Subsystem
  Mechanical Branching Bar : mblibv1/Utilities/Mechanical Branching Bar  LConnTagsString=_newl0  RConnTagsString=SA0|SA1  UpdateFromCAD=off  DialogClass=MechanicalBranchingBarBlock  NumSAPorts=2
  CS : PMIOPort  Port=1  Side=Right
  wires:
  Body Sensor/1 -> [posR_RearLeft], Contact Force/1(pos)
  Body Sensor/2 -> Contact Force/2(vel)
  Contact Force/1(force) -> Body Actuator/1
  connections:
  Mechanical Branching Bar/RConn1 -- Body Sensor/LConn1
  Mechanical Branching Bar/RConn2 -- Body Actuator/RConn1
  CS/RConn1 -- Mechanical Branching Bar/LConn1

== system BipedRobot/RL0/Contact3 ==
  Body Actuator : mblibv1/Sensors &  Actuators/Body Actuator  UpdateFromCAD=off  PhysicalDomain=Mechanical  PortType=blob  ActuationStyle=Force  AngleUnits=deg  ArcVelocityUnits=deg/s  ArcAccelerationUnits=deg/s^2  CoordPositionUnits=m  VelocityUnits=m/s  AccelerationUnits=m/s^2  ForceUnits=N  TorqueUnits=N-m  ActiveIO=on  Width=3  DialogClass=MechanicalActuatorBlock  ReferenceFrame=Absolute (World)  Angle=off  CoordPosition=on  Force=on  Torque=off
  Body Sensor : mblibv1/Sensors &  Actuators/Body Sensor  UpdateFromCAD=off  PhysicalDomain=Mechanical  PortType=blob  Muxed=off  Pose=off  Angle=on  AngleUnits=deg  ArcVelocity=off  ArcVelocityUnits=deg/s  ArcAcceleration=off  ArcAccelerationUnits=deg/s^2  CoordPosition=on  CoordPositionUnits=m  Velocity=on  VelocityUnits=m/s  Acceleration=off  AccelerationUnits=m/s^2  Quaternion=on  QuaternionDT=off  QuaternionDDT=off  QuaternionUnits=off  OutputVector=[ 3 3 ]  ActiveIO=on  Width=6  DialogClass=MechanicalSensorBlock  ReferenceFrame=Absolute (World)
  Contact Force : Subsystem
  Mechanical Branching Bar : mblibv1/Utilities/Mechanical Branching Bar  LConnTagsString=_newl0  RConnTagsString=SA0|SA1  UpdateFromCAD=off  DialogClass=MechanicalBranchingBarBlock  NumSAPorts=2
  CS : PMIOPort  Port=1  Side=Right
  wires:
  Body Sensor/1 -> [posR_FrontRight], Contact Force/1(pos)
  Body Sensor/2 -> Contact Force/2(vel)
  Contact Force/1(force) -> Body Actuator/1
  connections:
  Mechanical Branching Bar/RConn1 -- Body Sensor/LConn1
  Mechanical Branching Bar/RConn2 -- Body Actuator/RConn1
  CS/RConn1 -- Mechanical Branching Bar/LConn1

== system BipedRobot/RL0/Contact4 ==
  Body Actuator : mblibv1/Sensors &  Actuators/Body Actuator  UpdateFromCAD=off  PhysicalDomain=Mechanical  PortType=blob  ActuationStyle=Force  AngleUnits=deg  ArcVelocityUnits=deg/s  ArcAccelerationUnits=deg/s^2  CoordPositionUnits=m  VelocityUnits=m/s  AccelerationUnits=m/s^2  ForceUnits=N  TorqueUnits=N-m  ActiveIO=on  Width=3  DialogClass=MechanicalActuatorBlock  ReferenceFrame=Absolute (World)  Angle=off  CoordPosition=on  Force=on  Torque=off
  Body Sensor : mblibv1/Sensors &  Actuators/Body Sensor  UpdateFromCAD=off  PhysicalDomain=Mechanical  PortType=blob  Muxed=off  Pose=off  Angle=on  AngleUnits=deg  ArcVelocity=off  ArcVelocityUnits=deg/s  ArcAcceleration=off  ArcAccelerationUnits=deg/s^2  CoordPosition=on  CoordPositionUnits=m  Velocity=on  VelocityUnits=m/s  Acceleration=off  AccelerationUnits=m/s^2  Quaternion=on  QuaternionDT=off  QuaternionDDT=off  QuaternionUnits=off  OutputVector=[ 3 3 ]  ActiveIO=on  Width=6  DialogClass=MechanicalSensorBlock  ReferenceFrame=Absolute (World)
  Contact Force : Subsystem
  Mechanical Branching Bar : mblibv1/Utilities/Mechanical Branching Bar  LConnTagsString=_newl0  RConnTagsString=SA0|SA1  UpdateFromCAD=off  DialogClass=MechanicalBranchingBarBlock  NumSAPorts=2
  CS : PMIOPort  Port=1  Side=Right
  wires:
  Contact Force/1(force) -> Body Actuator/1
  Body Sensor/2 -> Contact Force/2(vel)
  Body Sensor/1 -> [posR_RearRight], Contact Force/1(pos)
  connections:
  CS/RConn1 -- Mechanical Branching Bar/LConn1
  Mechanical Branching Bar/RConn2 -- Body Actuator/RConn1
  Mechanical Branching Bar/RConn1 -- Body Sensor/LConn1

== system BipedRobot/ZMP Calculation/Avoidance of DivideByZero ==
  u : Inport
  Compare To Zero : simulink/Logic and Bit Operations/Compare To Zero  relop===  OutDataTypeStr=boolean  ZeroCross=off
  Constant : Constant
  Switch : Switch  Criteria=u2 > Threshold  Threshold=0.5
  y : Outport
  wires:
  Compare To Zero/1 -> Switch/2
  u/1 -> Compare To Zero/1, Switch/3
  Constant/1 -> Switch/1
  Switch/1 -> y/1

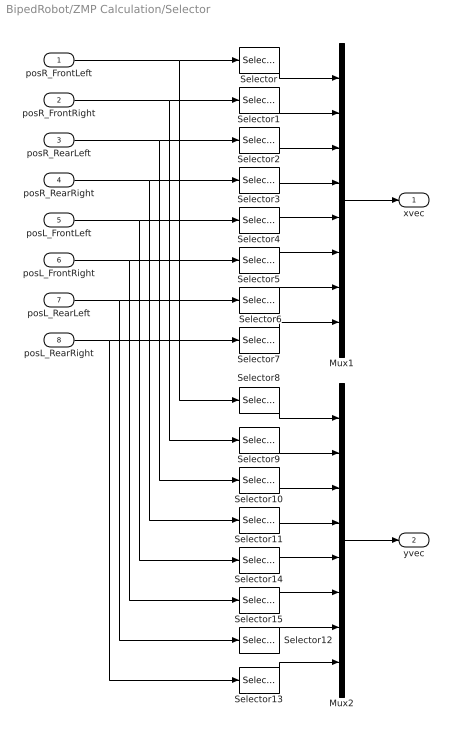
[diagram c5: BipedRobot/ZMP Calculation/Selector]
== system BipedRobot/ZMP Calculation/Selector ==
  posR_FrontLeft : Inport
  posR_FrontRight : Inport  Port=2
  posR_RearLeft : Inport  Port=3
  posR_RearRight : Inport  Port=4
  posL_FrontLeft : Inport  Port=5
  posL_FrontRight : Inport  Port=6
  posL_RearLeft : Inport  Port=7
  posL_RearRight : Inport  Port=8
  Mux1 : Mux  Inputs=8
  Mux2 : Mux  Inputs=8
  Selector{,1..7} (8 alike) : Selector  InputPortWidth=3  IndexOptions=Index vector (dialog)  Indices=1  OutputSizes=1
  Selector{8..15} (8 alike) : Selector  InputPortWidth=3  IndexOptions=Index vector (dialog)  Indices=2  OutputSizes=1
  xvec : Outport
  yvec : Outport  Port=2
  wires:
  posR_FrontLeft/1 -> Selector8/1, Selector/1
  posR_FrontRight/1 -> Selector9/1, Selector1/1
  posR_RearLeft/1 -> Selector10/1, Selector2/1
  posR_RearRight/1 -> Selector11/1, Selector3/1
  posL_FrontLeft/1 -> Selector14/1, Selector4/1
  posL_FrontRight/1 -> Selector15/1, Selector5/1
  posL_RearLeft/1 -> Selector12/1, Selector6/1
  posL_RearRight/1 -> Selector13/1, Selector7/1
  Selector/1 -> Mux1/1
  Selector1/1 -> Mux1/2
  Selector2/1 -> Mux1/3
  Selector3/1 -> Mux1/4
  Selector4/1 -> Mux1/5
  Selector5/1 -> Mux1/6
  Selector6/1 -> Mux1/7
  Selector7/1 -> Mux1/8
  Selector8/1 -> Mux2/1
  Selector9/1 -> Mux2/2
  Selector10/1 -> Mux2/3
  Selector11/1 -> Mux2/4
  Selector14/1 -> Mux2/5
  Selector15/1 -> Mux2/6
  Selector12/1 -> Mux2/7
  Selector13/1 -> Mux2/8
  Mux1/1 -> xvec/1
  Mux2/1 -> yvec/1

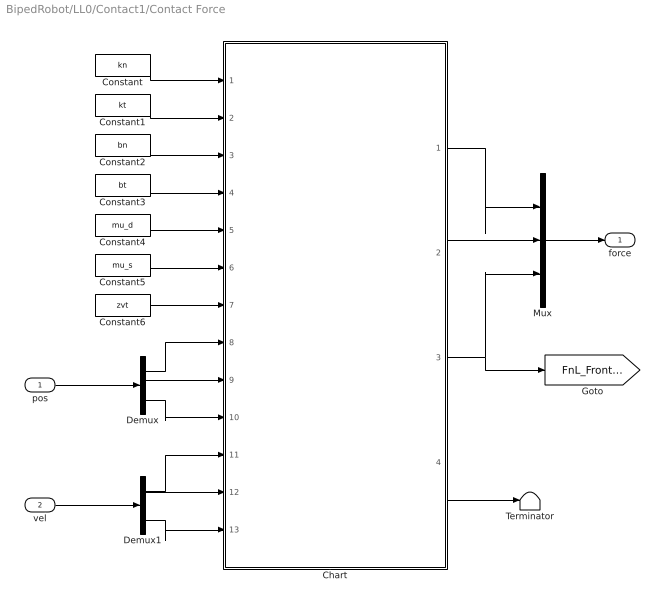
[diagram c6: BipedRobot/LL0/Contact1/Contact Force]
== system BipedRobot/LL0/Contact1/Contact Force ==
  pos : Inport
  vel : Inport  Port=2
  Chart : Stateflow chart  TreatAsAtomicUnit=on
  Constant : Constant  Value=kn
  Constant1 : Constant  Value=kt
  Constant2 : Constant  Value=bn
  Constant3 : Constant  Value=bt
  Constant4 : Constant  Value=mu_d
  Constant5 : Constant  Value=mu_s
  Constant6 : Constant  Value=zvt
  Demux : Demux  Outputs=3
  Demux1 : Demux  Outputs=3
  Mux : Mux  Inputs=3
  Terminator : Terminator
  force : Outport  InitialOutput=0
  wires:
  Chart/3(Fn) -> Mux/3, [FnL_FrontRight]
  Chart/2(Fy) -> Mux/2
  Chart/1(Fx) -> Mux/1
  vel/1 -> Demux1/1
  pos/1 -> Demux/1
  Demux1/3 -> Chart/13(dpn)
  Demux1/2 -> Chart/12(dpy)
  Demux1/1 -> Chart/11(dpx)
  Demux/3 -> Chart/10(pn)
  Demux/2 -> Chart/9(py)
  Demux/1 -> Chart/8(px)
  Chart/4(mode) -> Terminator/1
  Mux/1 -> force/1
  Constant/1 -> Chart/1(kn)
  Constant1/1 -> Chart/2(kt)
  Constant2/1 -> Chart/3(bn)
  Constant3/1 -> Chart/4(bt)
  Constant4/1 -> Chart/5(mu_d)
  Constant5/1 -> Chart/6(mu_s)
  Constant6/1 -> Chart/7(zvt)

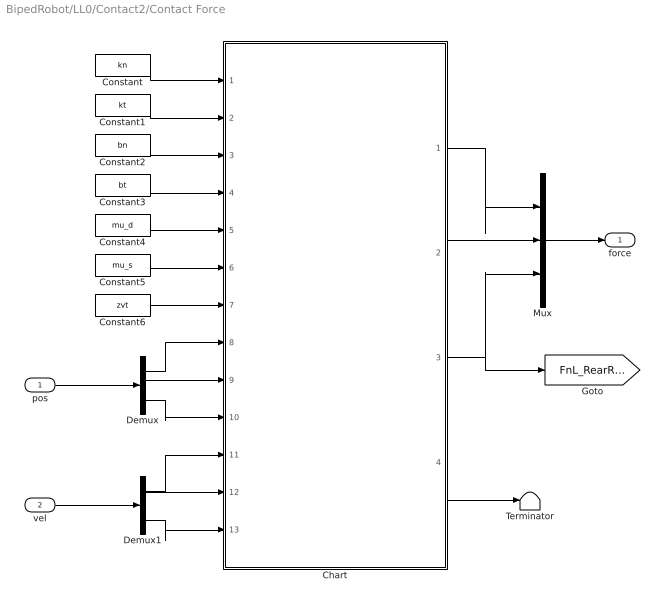
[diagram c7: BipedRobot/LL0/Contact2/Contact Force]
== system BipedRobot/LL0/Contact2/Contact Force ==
  pos : Inport
  vel : Inport  Port=2
  Chart : Stateflow chart  TreatAsAtomicUnit=on
  Constant : Constant  Value=kn
  Constant1 : Constant  Value=kt
  Constant2 : Constant  Value=bn
  Constant3 : Constant  Value=bt
  Constant4 : Constant  Value=mu_d
  Constant5 : Constant  Value=mu_s
  Constant6 : Constant  Value=zvt
  Demux : Demux  Outputs=3
  Demux1 : Demux  Outputs=3
  Mux : Mux  Inputs=3
  Terminator : Terminator
  force : Outport  InitialOutput=0
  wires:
  Chart/3(Fn) -> Mux/3, [FnL_RearRight]
  Chart/2(Fy) -> Mux/2
  Chart/1(Fx) -> Mux/1
  vel/1 -> Demux1/1
  pos/1 -> Demux/1
  Demux1/3 -> Chart/13(dpn)
  Demux1/2 -> Chart/12(dpy)
  Demux1/1 -> Chart/11(dpx)
  Demux/3 -> Chart/10(pn)
  Demux/2 -> Chart/9(py)
  Demux/1 -> Chart/8(px)
  Chart/4(mode) -> Terminator/1
  Mux/1 -> force/1
  Constant/1 -> Chart/1(kn)
  Constant1/1 -> Chart/2(kt)
  Constant2/1 -> Chart/3(bn)
  Constant3/1 -> Chart/4(bt)
  Constant4/1 -> Chart/5(mu_d)
  Constant5/1 -> Chart/6(mu_s)
  Constant6/1 -> Chart/7(zvt)

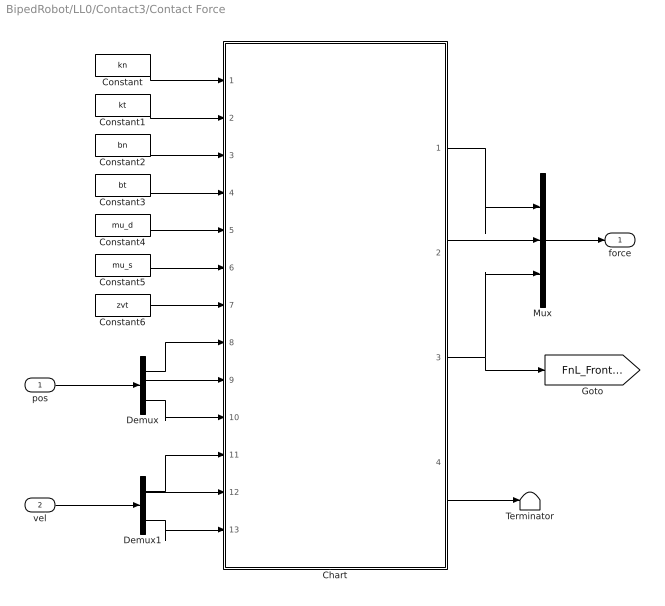
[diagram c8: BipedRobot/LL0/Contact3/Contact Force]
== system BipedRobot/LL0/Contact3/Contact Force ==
  pos : Inport
  vel : Inport  Port=2
  Chart : Stateflow chart  TreatAsAtomicUnit=on
  Constant : Constant  Value=kn
  Constant1 : Constant  Value=kt
  Constant2 : Constant  Value=bn
  Constant3 : Constant  Value=bt
  Constant4 : Constant  Value=mu_d
  Constant5 : Constant  Value=mu_s
  Constant6 : Constant  Value=zvt
  Demux : Demux  Outputs=3
  Demux1 : Demux  Outputs=3
  Mux : Mux  Inputs=3
  Terminator : Terminator
  force : Outport  InitialOutput=0
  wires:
  Chart/3(Fn) -> Mux/3, [FnL_FrontLeft]
  Chart/2(Fy) -> Mux/2
  Chart/1(Fx) -> Mux/1
  vel/1 -> Demux1/1
  pos/1 -> Demux/1
  Demux1/3 -> Chart/13(dpn)
  Demux1/2 -> Chart/12(dpy)
  Demux1/1 -> Chart/11(dpx)
  Demux/3 -> Chart/10(pn)
  Demux/2 -> Chart/9(py)
  Demux/1 -> Chart/8(px)
  Chart/4(mode) -> Terminator/1
  Mux/1 -> force/1
  Constant/1 -> Chart/1(kn)
  Constant1/1 -> Chart/2(kt)
  Constant2/1 -> Chart/3(bn)
  Constant3/1 -> Chart/4(bt)
  Constant4/1 -> Chart/5(mu_d)
  Constant5/1 -> Chart/6(mu_s)
  Constant6/1 -> Chart/7(zvt)

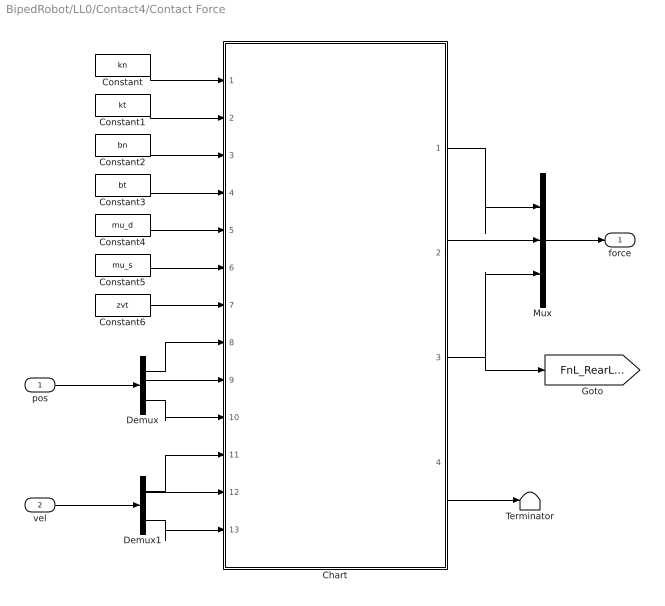
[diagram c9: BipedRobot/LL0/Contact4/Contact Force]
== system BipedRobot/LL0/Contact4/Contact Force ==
  pos : Inport
  vel : Inport  Port=2
  Chart : Stateflow chart  TreatAsAtomicUnit=on
  Constant : Constant  Value=kn
  Constant1 : Constant  Value=kt
  Constant2 : Constant  Value=bn
  Constant3 : Constant  Value=bt
  Constant4 : Constant  Value=mu_d
  Constant5 : Constant  Value=mu_s
  Constant6 : Constant  Value=zvt
  Demux : Demux  Outputs=3
  Demux1 : Demux  Outputs=3
  Mux : Mux  Inputs=3
  Terminator : Terminator
  force : Outport  InitialOutput=0
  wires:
  Chart/3(Fn) -> Mux/3, [FnL_RearLeft]
  Chart/2(Fy) -> Mux/2
  Chart/1(Fx) -> Mux/1
  vel/1 -> Demux1/1
  pos/1 -> Demux/1
  Demux1/3 -> Chart/13(dpn)
  Demux1/2 -> Chart/12(dpy)
  Demux1/1 -> Chart/11(dpx)
  Demux/3 -> Chart/10(pn)
  Demux/2 -> Chart/9(py)
  Demux/1 -> Chart/8(px)
  Chart/4(mode) -> Terminator/1
  Mux/1 -> force/1
  Constant/1 -> Chart/1(kn)
  Constant1/1 -> Chart/2(kt)
  Constant2/1 -> Chart/3(bn)
  Constant3/1 -> Chart/4(bt)
  Constant4/1 -> Chart/5(mu_d)
  Constant5/1 -> Chart/6(mu_s)
  Constant6/1 -> Chart/7(zvt)

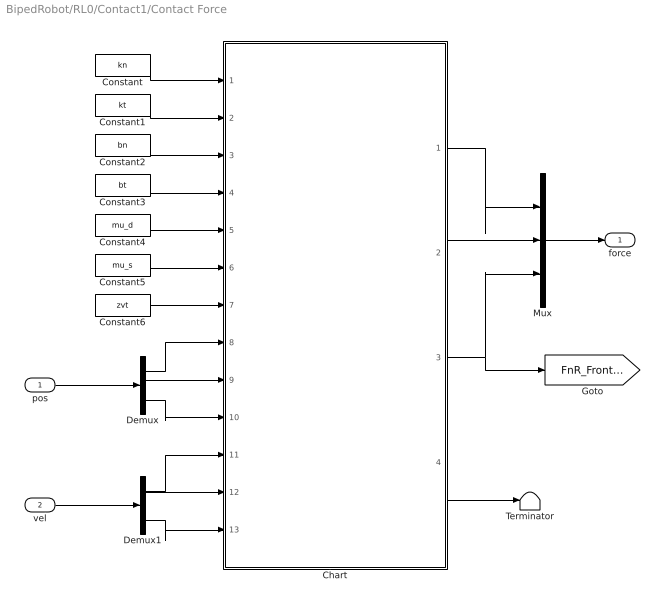
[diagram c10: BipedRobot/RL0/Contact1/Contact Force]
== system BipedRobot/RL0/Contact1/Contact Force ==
  pos : Inport
  vel : Inport  Port=2
  Chart : Stateflow chart  TreatAsAtomicUnit=on
  Constant : Constant  Value=kn
  Constant1 : Constant  Value=kt
  Constant2 : Constant  Value=bn
  Constant3 : Constant  Value=bt
  Constant4 : Constant  Value=mu_d
  Constant5 : Constant  Value=mu_s
  Constant6 : Constant  Value=zvt
  Demux : Demux  Outputs=3
  Demux1 : Demux  Outputs=3
  Mux : Mux  Inputs=3
  Terminator : Terminator
  force : Outport  InitialOutput=0
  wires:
  Chart/3(Fn) -> Mux/3, [FnR_FrontLeft]
  Chart/2(Fy) -> Mux/2
  Chart/1(Fx) -> Mux/1
  vel/1 -> Demux1/1
  pos/1 -> Demux/1
  Demux1/3 -> Chart/13(dpn)
  Demux1/2 -> Chart/12(dpy)
  Demux1/1 -> Chart/11(dpx)
  Demux/3 -> Chart/10(pn)
  Demux/2 -> Chart/9(py)
  Demux/1 -> Chart/8(px)
  Chart/4(mode) -> Terminator/1
  Mux/1 -> force/1
  Constant/1 -> Chart/1(kn)
  Constant1/1 -> Chart/2(kt)
  Constant2/1 -> Chart/3(bn)
  Constant3/1 -> Chart/4(bt)
  Constant4/1 -> Chart/5(mu_d)
  Constant5/1 -> Chart/6(mu_s)
  Constant6/1 -> Chart/7(zvt)

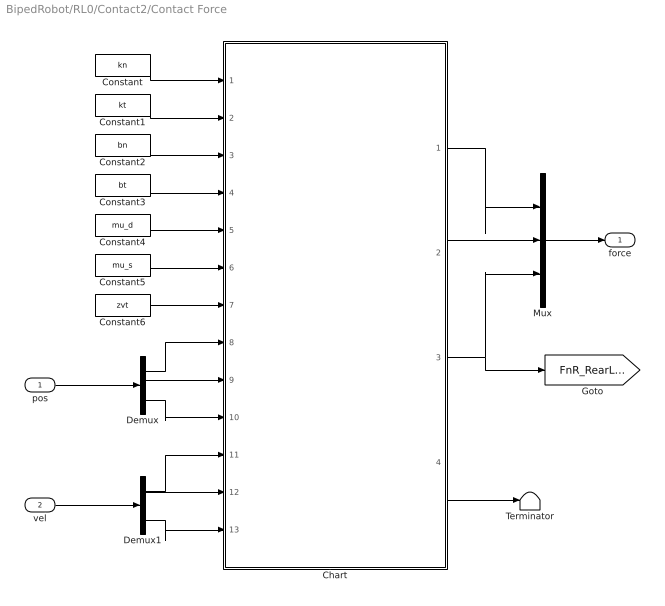
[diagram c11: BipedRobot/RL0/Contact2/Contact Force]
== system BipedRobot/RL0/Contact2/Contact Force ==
  pos : Inport
  vel : Inport  Port=2
  Chart : Stateflow chart  TreatAsAtomicUnit=on
  Constant : Constant  Value=kn
  Constant1 : Constant  Value=kt
  Constant2 : Constant  Value=bn
  Constant3 : Constant  Value=bt
  Constant4 : Constant  Value=mu_d
  Constant5 : Constant  Value=mu_s
  Constant6 : Constant  Value=zvt
  Demux : Demux  Outputs=3
  Demux1 : Demux  Outputs=3
  Mux : Mux  Inputs=3
  Terminator : Terminator
  force : Outport  InitialOutput=0
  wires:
  Chart/3(Fn) -> Mux/3, [FnR_RearLeft]
  Chart/2(Fy) -> Mux/2
  Chart/1(Fx) -> Mux/1
  vel/1 -> Demux1/1
  pos/1 -> Demux/1
  Demux1/3 -> Chart/13(dpn)
  Demux1/2 -> Chart/12(dpy)
  Demux1/1 -> Chart/11(dpx)
  Demux/3 -> Chart/10(pn)
  Demux/2 -> Chart/9(py)
  Demux/1 -> Chart/8(px)
  Chart/4(mode) -> Terminator/1
  Mux/1 -> force/1
  Constant/1 -> Chart/1(kn)
  Constant1/1 -> Chart/2(kt)
  Constant2/1 -> Chart/3(bn)
  Constant3/1 -> Chart/4(bt)
  Constant4/1 -> Chart/5(mu_d)
  Constant5/1 -> Chart/6(mu_s)
  Constant6/1 -> Chart/7(zvt)

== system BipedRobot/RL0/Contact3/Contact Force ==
  pos : Inport
  vel : Inport  Port=2
  Chart : Stateflow chart  TreatAsAtomicUnit=on
  Constant : Constant  Value=kn
  Constant1 : Constant  Value=kt
  Constant2 : Constant  Value=bn
  Constant3 : Constant  Value=bt
  Constant4 : Constant  Value=mu_d
  Constant5 : Constant  Value=mu_s
  Constant6 : Constant  Value=zvt
  Demux : Demux  Outputs=3
  Demux1 : Demux  Outputs=3
  Mux : Mux  Inputs=3
  Terminator : Terminator
  force : Outport  InitialOutput=0
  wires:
  Chart/3(Fn) -> Mux/3, [FnR_FrontRight]
  Chart/2(Fy) -> Mux/2
  Chart/1(Fx) -> Mux/1
  vel/1 -> Demux1/1
  pos/1 -> Demux/1
  Demux1/3 -> Chart/13(dpn)
  Demux1/2 -> Chart/12(dpy)
  Demux1/1 -> Chart/11(dpx)
  Demux/3 -> Chart/10(pn)
  Demux/2 -> Chart/9(py)
  Demux/1 -> Chart/8(px)
  Chart/4(mode) -> Terminator/1
  Mux/1 -> force/1
  Constant/1 -> Chart/1(kn)
  Constant1/1 -> Chart/2(kt)
  Constant2/1 -> Chart/3(bn)
  Constant3/1 -> Chart/4(bt)
  Constant4/1 -> Chart/5(mu_d)
  Constant5/1 -> Chart/6(mu_s)
  Constant6/1 -> Chart/7(zvt)

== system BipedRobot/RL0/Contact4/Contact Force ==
  pos : Inport
  vel : Inport  Port=2
  Chart : Stateflow chart  TreatAsAtomicUnit=on
  Constant : Constant  Value=kn
  Constant1 : Constant  Value=kt
  Constant2 : Constant  Value=bn
  Constant3 : Constant  Value=bt
  Constant4 : Constant  Value=mu_d
  Constant5 : Constant  Value=mu_s
  Constant6 : Constant  Value=zvt
  Demux : Demux  Outputs=3
  Demux1 : Demux  Outputs=3
  Mux : Mux  Inputs=3
  Terminator : Terminator
  force : Outport  InitialOutput=0
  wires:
  Chart/3(Fn) -> Mux/3, [FnR_RearRight]
  Chart/2(Fy) -> Mux/2
  Chart/1(Fx) -> Mux/1
  vel/1 -> Demux1/1
  pos/1 -> Demux/1
  Demux1/3 -> Chart/13(dpn)
  Demux1/2 -> Chart/12(dpy)
  Demux1/1 -> Chart/11(dpx)
  Demux/3 -> Chart/10(pn)
  Demux/2 -> Chart/9(py)
  Demux/1 -> Chart/8(px)
  Chart/4(mode) -> Terminator/1
  Mux/1 -> force/1
  Constant/1 -> Chart/1(kn)
  Constant1/1 -> Chart/2(kt)
  Constant2/1 -> Chart/3(bn)
  Constant3/1 -> Chart/4(bt)
  Constant4/1 -> Chart/5(mu_d)
  Constant5/1 -> Chart/6(mu_s)
  Constant6/1 -> Chart/7(zvt)

== stateflow chart BipedRobot/RL0/Contact1/Contact
Force/Chart ==
  state No_Contact/
    state 非接触状態 [group]
    (default) -> (junction 48) : { mode = 1;  /* 垂直力、摩擦力ともにゼロ */ Fn = 0; Fx = 0; Fy = 0; }
  state Sticking/
    state 固着状態 [group]
    Sticking -> (junction 53) : { /* 垂直力計算 */ Fn = -(kn*pn+bn*dpn); }
    (default) -> (junction 52) : { mode = 4;  /* 垂直力計算 */ Fn = -(kn*pn+bn*dpn); }
    (junction 52) -> (junction 53)
    (junction 53) -> (junction 54) : [ Fn < 0 ]
    (junction 53) -> (junction 41) : { /* 静止摩擦力計算 */ Fx = -(kt*(px-ax)+bt*dpx); Fy = -(kt*(py-ay)+bt*dpy);  /* 摩擦力ベクトルの大きさ */ norm_Ft = sqrt(Fx^2+Fy^2); }
    (junction 54) -> (junction 47) : { mode = 6;  /* 垂直力が負のときの処理 垂直力、摩擦力をゼロへ */ Fn = 0; Fx = 0; Fy = 0; }
    (junction 41) -> (junction 40) : [ norm_Ft > mu_s*Fn ]
    (junction 41) -> (junction 39)
    (junction 40) -> (junction 38) : { mode = 5;  /* 静止摩擦力計算 */ Fx = -mu_s*Fn*Fx/norm_Ft; Fy = -mu_s*Fn*Fy/norm_Ft; }
    (junction 38) -> (junction 39)
    (junction 47) -> (junction 38)
    (junction 39) -> (junction 56)
  state Sliding/
    state 滑り状態 [group]
    Sliding -> (junction 43) : { mode = 2;  /* 垂直力計算 */ Fn = -(kn*pn+bn*dpn); }
    (default) -> (junction 42) : { mode = 2;  /* 垂直力計算 */ Fn = -(kn*pn+bn*dpn); }
    (junction 42) -> (junction 43)
    (junction 43) -> (junction 44) : [ Fn < 0 ]
    (junction 43) -> (junction 45) : { /* 接線方向速度ベクトルの大きさ */ norm_dpt = sqrt(dpx^2+dpy^2); }
    (junction 44) -> (junction 46) : { mode = 6;  /* 垂直力が負のときの処理 垂直力、摩擦力をゼロへ */ Fn = 0; Fx = 0; Fy = 0; }
    (junction 45) -> (junction 49) : [ norm_dpt <= zvt ]
    (junction 45) -> (junction 51) : { /* 動摩擦力計算 */ Fx = -mu_d*Fn*dpx/norm_dpt; Fy = -mu_d*Fn*dpy/norm_dpt; }
    (junction 49) -> (junction 50) : { mode = 3;  /* 動摩擦力計算 */ Fx = -mu_d*Fn*dpx/zvt; Fy = -mu_d*Fn*dpy/zvt;  /* アンカーポイント設定 */ ax = px; ay = py; }
    (junction 50) -> (junction 51)
    (junction 46) -> (junction 50)
    (junction 51) -> (junction 55)
  (default) -> No_Contact
  Sliding -> No_Contact : [pn >= 0 ]
  No_Contact -> Sliding : [ pn < 0 ]
  Sticking -> No_Contact : [ pn >= 0 ]
  Sliding -> Sticking : [ pn < 0 ... && mode == 3 ]
  Sticking -> Sliding : [ pn < 0 ... && (mode == 5 || mode == 6) ]
  data: Fx output double; Fy output double; kn input =kn; kt input =kt; bn input =bn; bt input =bt; mu_d input =mu_d; mu_s input =mu_s; zvt input =zvt; px input; py input; pn input; dpx input; dpy input; Fn output double; dpn input; norm_dpt local double; norm_Ft local double; mode output double; ax local double; ay local double

== stateflow chart BipedRobot/RL0/Contact2/Contact
Force/Chart ==
  state No_Contact/
    state 非接触状態 [group]
    (default) -> (junction 48) : { mode = 1;  /* 垂直力、摩擦力ともにゼロ */ Fn = 0; Fx = 0; Fy = 0; }
  state Sticking/
    state 固着状態 [group]
    Sticking -> (junction 53) : { /* 垂直力計算 */ Fn = -(kn*pn+bn*dpn); }
    (default) -> (junction 52) : { mode = 4;  /* 垂直力計算 */ Fn = -(kn*pn+bn*dpn); }
    (junction 52) -> (junction 53)
    (junction 53) -> (junction 54) : [ Fn < 0 ]
    (junction 53) -> (junction 41) : { /* 静止摩擦力計算 */ Fx = -(kt*(px-ax)+bt*dpx); Fy = -(kt*(py-ay)+bt*dpy);  /* 摩擦力ベクトルの大きさ */ norm_Ft = sqrt(Fx^2+Fy^2); }
    (junction 54) -> (junction 47) : { mode = 6;  /* 垂直力が負のときの処理 垂直力、摩擦力をゼロへ */ Fn = 0; Fx = 0; Fy = 0; }
    (junction 41) -> (junction 40) : [ norm_Ft > mu_s*Fn ]
    (junction 41) -> (junction 39)
    (junction 40) -> (junction 38) : { mode = 5;  /* 静止摩擦力計算 */ Fx = -mu_s*Fn*Fx/norm_Ft; Fy = -mu_s*Fn*Fy/norm_Ft; }
    (junction 38) -> (junction 39)
    (junction 47) -> (junction 38)
    (junction 39) -> (junction 56)
  state Sliding/
    state 滑り状態 [group]
    Sliding -> (junction 43) : { mode = 2;  /* 垂直力計算 */ Fn = -(kn*pn+bn*dpn); }
    (default) -> (junction 42) : { mode = 2;  /* 垂直力計算 */ Fn = -(kn*pn+bn*dpn); }
    (junction 42) -> (junction 43)
    (junction 43) -> (junction 44) : [ Fn < 0 ]
    (junction 43) -> (junction 45) : { /* 接線方向速度ベクトルの大きさ */ norm_dpt = sqrt(dpx^2+dpy^2); }
    (junction 44) -> (junction 46) : { mode = 6;  /* 垂直力が負のときの処理 垂直力、摩擦力をゼロへ */ Fn = 0; Fx = 0; Fy = 0; }
    (junction 45) -> (junction 49) : [ norm_dpt <= zvt ]
    (junction 45) -> (junction 51) : { /* 動摩擦力計算 */ Fx = -mu_d*Fn*dpx/norm_dpt; Fy = -mu_d*Fn*dpy/norm_dpt; }
    (junction 49) -> (junction 50) : { mode = 3;  /* 動摩擦力計算 */ Fx = -mu_d*Fn*dpx/zvt; Fy = -mu_d*Fn*dpy/zvt;  /* アンカーポイント設定 */ ax = px; ay = py; }
    (junction 50) -> (junction 51)
    (junction 46) -> (junction 50)
    (junction 51) -> (junction 55)
  (default) -> No_Contact
  Sliding -> No_Contact : [pn >= 0 ]
  No_Contact -> Sliding : [ pn < 0 ]
  Sticking -> No_Contact : [ pn >= 0 ]
  Sliding -> Sticking : [ pn < 0 ... && mode == 3 ]
  Sticking -> Sliding : [ pn < 0 ... && (mode == 5 || mode == 6) ]
  data: Fx output double; Fy output double; kn input =kn; kt input =kt; bn input =bn; bt input =bt; mu_d input =mu_d; mu_s input =mu_s; zvt input =zvt; px input; py input; pn input; dpx input; dpy input; Fn output double; dpn input; norm_dpt local double; norm_Ft local double; mode output double; ax local double; ay local double

== stateflow chart BipedRobot/RL0/Contact3/Contact
Force/Chart ==
  state No_Contact/
    state 非接触状態 [group]
    (default) -> (junction 48) : { mode = 1;  /* 垂直力、摩擦力ともにゼロ */ Fn = 0; Fx = 0; Fy = 0; }
  state Sticking/
    state 固着状態 [group]
    Sticking -> (junction 53) : { /* 垂直力計算 */ Fn = -(kn*pn+bn*dpn); }
    (default) -> (junction 52) : { mode = 4;  /* 垂直力計算 */ Fn = -(kn*pn+bn*dpn); }
    (junction 52) -> (junction 53)
    (junction 53) -> (junction 54) : [ Fn < 0 ]
    (junction 53) -> (junction 41) : { /* 静止摩擦力計算 */ Fx = -(kt*(px-ax)+bt*dpx); Fy = -(kt*(py-ay)+bt*dpy);  /* 摩擦力ベクトルの大きさ */ norm_Ft = sqrt(Fx^2+Fy^2); }
    (junction 54) -> (junction 47) : { mode = 6;  /* 垂直力が負のときの処理 垂直力、摩擦力をゼロへ */ Fn = 0; Fx = 0; Fy = 0; }
    (junction 41) -> (junction 40) : [ norm_Ft > mu_s*Fn ]
    (junction 41) -> (junction 39)
    (junction 40) -> (junction 38) : { mode = 5;  /* 静止摩擦力計算 */ Fx = -mu_s*Fn*Fx/norm_Ft; Fy = -mu_s*Fn*Fy/norm_Ft; }
    (junction 38) -> (junction 39)
    (junction 47) -> (junction 38)
    (junction 39) -> (junction 56)
  state Sliding/
    state 滑り状態 [group]
    Sliding -> (junction 43) : { mode = 2;  /* 垂直力計算 */ Fn = -(kn*pn+bn*dpn); }
    (default) -> (junction 42) : { mode = 2;  /* 垂直力計算 */ Fn = -(kn*pn+bn*dpn); }
    (junction 42) -> (junction 43)
    (junction 43) -> (junction 44) : [ Fn < 0 ]
    (junction 43) -> (junction 45) : { /* 接線方向速度ベクトルの大きさ */ norm_dpt = sqrt(dpx^2+dpy^2); }
    (junction 44) -> (junction 46) : { mode = 6;  /* 垂直力が負のときの処理 垂直力、摩擦力をゼロへ */ Fn = 0; Fx = 0; Fy = 0; }
    (junction 45) -> (junction 49) : [ norm_dpt <= zvt ]
    (junction 45) -> (junction 51) : { /* 動摩擦力計算 */ Fx = -mu_d*Fn*dpx/norm_dpt; Fy = -mu_d*Fn*dpy/norm_dpt; }
    (junction 49) -> (junction 50) : { mode = 3;  /* 動摩擦力計算 */ Fx = -mu_d*Fn*dpx/zvt; Fy = -mu_d*Fn*dpy/zvt;  /* アンカーポイント設定 */ ax = px; ay = py; }
    (junction 50) -> (junction 51)
    (junction 46) -> (junction 50)
    (junction 51) -> (junction 55)
  (default) -> No_Contact
  Sliding -> No_Contact : [pn >= 0 ]
  No_Contact -> Sliding : [ pn < 0 ]
  Sticking -> No_Contact : [ pn >= 0 ]
  Sliding -> Sticking : [ pn < 0 ... && mode == 3 ]
  Sticking -> Sliding : [ pn < 0 ... && (mode == 5 || mode == 6) ]
  data: Fx output double; Fy output double; kn input =kn; kt input =kt; bn input =bn; bt input =bt; mu_d input =mu_d; mu_s input =mu_s; zvt input =zvt; px input; py input; pn input; dpx input; dpy input; Fn output double; dpn input; norm_dpt local double; norm_Ft local double; mode output double; ax local double; ay local double

== stateflow chart BipedRobot/RL0/Contact4/Contact
Force/Chart ==
  state No_Contact/
    state 非接触状態 [group]
    (default) -> (junction 48) : { mode = 1;  /* 垂直力、摩擦力ともにゼロ */ Fn = 0; Fx = 0; Fy = 0; }
  state Sticking/
    state 固着状態 [group]
    Sticking -> (junction 53) : { /* 垂直力計算 */ Fn = -(kn*pn+bn*dpn); }
    (default) -> (junction 52) : { mode = 4;  /* 垂直力計算 */ Fn = -(kn*pn+bn*dpn); }
    (junction 52) -> (junction 53)
    (junction 53) -> (junction 54) : [ Fn < 0 ]
    (junction 53) -> (junction 41) : { /* 静止摩擦力計算 */ Fx = -(kt*(px-ax)+bt*dpx); Fy = -(kt*(py-ay)+bt*dpy);  /* 摩擦力ベクトルの大きさ */ norm_Ft = sqrt(Fx^2+Fy^2); }
    (junction 54) -> (junction 47) : { mode = 6;  /* 垂直力が負のときの処理 垂直力、摩擦力をゼロへ */ Fn = 0; Fx = 0; Fy = 0; }
    (junction 41) -> (junction 40) : [ norm_Ft > mu_s*Fn ]
    (junction 41) -> (junction 39)
    (junction 40) -> (junction 38) : { mode = 5;  /* 静止摩擦力計算 */ Fx = -mu_s*Fn*Fx/norm_Ft; Fy = -mu_s*Fn*Fy/norm_Ft; }
    (junction 38) -> (junction 39)
    (junction 47) -> (junction 38)
    (junction 39) -> (junction 56)
  state Sliding/
    state 滑り状態 [group]
    Sliding -> (junction 43) : { mode = 2;  /* 垂直力計算 */ Fn = -(kn*pn+bn*dpn); }
    (default) -> (junction 42) : { mode = 2;  /* 垂直力計算 */ Fn = -(kn*pn+bn*dpn); }
    (junction 42) -> (junction 43)
    (junction 43) -> (junction 44) : [ Fn < 0 ]
    (junction 43) -> (junction 45) : { /* 接線方向速度ベクトルの大きさ */ norm_dpt = sqrt(dpx^2+dpy^2); }
    (junction 44) -> (junction 46) : { mode = 6;  /* 垂直力が負のときの処理 垂直力、摩擦力をゼロへ */ Fn = 0; Fx = 0; Fy = 0; }
    (junction 45) -> (junction 49) : [ norm_dpt <= zvt ]
    (junction 45) -> (junction 51) : { /* 動摩擦力計算 */ Fx = -mu_d*Fn*dpx/norm_dpt; Fy = -mu_d*Fn*dpy/norm_dpt; }
    (junction 49) -> (junction 50) : { mode = 3;  /* 動摩擦力計算 */ Fx = -mu_d*Fn*dpx/zvt; Fy = -mu_d*Fn*dpy/zvt;  /* アンカーポイント設定 */ ax = px; ay = py; }
    (junction 50) -> (junction 51)
    (junction 46) -> (junction 50)
    (junction 51) -> (junction 55)
  (default) -> No_Contact
  Sliding -> No_Contact : [pn >= 0 ]
  No_Contact -> Sliding : [ pn < 0 ]
  Sticking -> No_Contact : [ pn >= 0 ]
  Sliding -> Sticking : [ pn < 0 ... && mode == 3 ]
  Sticking -> Sliding : [ pn < 0 ... && (mode == 5 || mode == 6) ]
  data: Fx output double; Fy output double; kn input =kn; kt input =kt; bn input =bn; bt input =bt; mu_d input =mu_d; mu_s input =mu_s; zvt input =zvt; px input; py input; pn input; dpx input; dpy input; Fn output double; dpn input; norm_dpt local double; norm_Ft local double; mode output double; ax local double; ay local double

== stateflow chart BipedRobot/LL0/Contact1/Contact
Force/Chart ==
  state No_Contact/
    state 非接触状態 [group]
    (default) -> (junction 48) : { mode = 1;  /* 垂直力、摩擦力ともにゼロ */ Fn = 0; Fx = 0; Fy = 0; }
  state Sticking/
    state 固着状態 [group]
    Sticking -> (junction 53) : { /* 垂直力計算 */ Fn = -(kn*pn+bn*dpn); }
    (default) -> (junction 52) : { mode = 4;  /* 垂直力計算 */ Fn = -(kn*pn+bn*dpn); }
    (junction 52) -> (junction 53)
    (junction 53) -> (junction 54) : [ Fn < 0 ]
    (junction 53) -> (junction 41) : { /* 静止摩擦力計算 */ Fx = -(kt*(px-ax)+bt*dpx); Fy = -(kt*(py-ay)+bt*dpy);  /* 摩擦力ベクトルの大きさ */ norm_Ft = sqrt(Fx^2+Fy^2); }
    (junction 54) -> (junction 47) : { mode = 6;  /* 垂直力が負のときの処理 垂直力、摩擦力をゼロへ */ Fn = 0; Fx = 0; Fy = 0; }
    (junction 41) -> (junction 40) : [ norm_Ft > mu_s*Fn ]
    (junction 41) -> (junction 39)
    (junction 40) -> (junction 38) : { mode = 5;  /* 静止摩擦力計算 */ Fx = -mu_s*Fn*Fx/norm_Ft; Fy = -mu_s*Fn*Fy/norm_Ft; }
    (junction 38) -> (junction 39)
    (junction 47) -> (junction 38)
    (junction 39) -> (junction 56)
  state Sliding/
    state 滑り状態 [group]
    Sliding -> (junction 43) : { mode = 2;  /* 垂直力計算 */ Fn = -(kn*pn+bn*dpn); }
    (default) -> (junction 42) : { mode = 2;  /* 垂直力計算 */ Fn = -(kn*pn+bn*dpn); }
    (junction 42) -> (junction 43)
    (junction 43) -> (junction 44) : [ Fn < 0 ]
    (junction 43) -> (junction 45) : { /* 接線方向速度ベクトルの大きさ */ norm_dpt = sqrt(dpx^2+dpy^2); }
    (junction 44) -> (junction 46) : { mode = 6;  /* 垂直力が負のときの処理 垂直力、摩擦力をゼロへ */ Fn = 0; Fx = 0; Fy = 0; }
    (junction 45) -> (junction 49) : [ norm_dpt <= zvt ]
    (junction 45) -> (junction 51) : { /* 動摩擦力計算 */ Fx = -mu_d*Fn*dpx/norm_dpt; Fy = -mu_d*Fn*dpy/norm_dpt; }
    (junction 49) -> (junction 50) : { mode = 3;  /* 動摩擦力計算 */ Fx = -mu_d*Fn*dpx/zvt; Fy = -mu_d*Fn*dpy/zvt;  /* アンカーポイント設定 */ ax = px; ay = py; }
    (junction 50) -> (junction 51)
    (junction 46) -> (junction 50)
    (junction 51) -> (junction 55)
  (default) -> No_Contact
  Sliding -> No_Contact : [pn >= 0 ]
  No_Contact -> Sliding : [ pn < 0 ]
  Sticking -> No_Contact : [ pn >= 0 ]
  Sliding -> Sticking : [ pn < 0 ... && mode == 3 ]
  Sticking -> Sliding : [ pn < 0 ... && (mode == 5 || mode == 6) ]
  data: Fx output double; Fy output double; kn input =kn; kt input =kt; bn input =bn; bt input =bt; mu_d input =mu_d; mu_s input =mu_s; zvt input =zvt; px input; py input; pn input; dpx input; dpy input; Fn output double; dpn input; norm_dpt local double; norm_Ft local double; mode output double; ax local double; ay local double

== stateflow chart BipedRobot/LL0/Contact2/Contact
Force/Chart ==
  state No_Contact/
    state 非接触状態 [group]
    (default) -> (junction 48) : { mode = 1;  /* 垂直力、摩擦力ともにゼロ */ Fn = 0; Fx = 0; Fy = 0; }
  state Sticking/
    state 固着状態 [group]
    Sticking -> (junction 53) : { /* 垂直力計算 */ Fn = -(kn*pn+bn*dpn); }
    (default) -> (junction 52) : { mode = 4;  /* 垂直力計算 */ Fn = -(kn*pn+bn*dpn); }
    (junction 52) -> (junction 53)
    (junction 53) -> (junction 54) : [ Fn < 0 ]
    (junction 53) -> (junction 41) : { /* 静止摩擦力計算 */ Fx = -(kt*(px-ax)+bt*dpx); Fy = -(kt*(py-ay)+bt*dpy);  /* 摩擦力ベクトルの大きさ */ norm_Ft = sqrt(Fx^2+Fy^2); }
    (junction 54) -> (junction 47) : { mode = 6;  /* 垂直力が負のときの処理 垂直力、摩擦力をゼロへ */ Fn = 0; Fx = 0; Fy = 0; }
    (junction 41) -> (junction 40) : [ norm_Ft > mu_s*Fn ]
    (junction 41) -> (junction 39)
    (junction 40) -> (junction 38) : { mode = 5;  /* 静止摩擦力計算 */ Fx = -mu_s*Fn*Fx/norm_Ft; Fy = -mu_s*Fn*Fy/norm_Ft; }
    (junction 38) -> (junction 39)
    (junction 47) -> (junction 38)
    (junction 39) -> (junction 56)
  state Sliding/
    state 滑り状態 [group]
    Sliding -> (junction 43) : { mode = 2;  /* 垂直力計算 */ Fn = -(kn*pn+bn*dpn); }
    (default) -> (junction 42) : { mode = 2;  /* 垂直力計算 */ Fn = -(kn*pn+bn*dpn); }
    (junction 42) -> (junction 43)
    (junction 43) -> (junction 44) : [ Fn < 0 ]
    (junction 43) -> (junction 45) : { /* 接線方向速度ベクトルの大きさ */ norm_dpt = sqrt(dpx^2+dpy^2); }
    (junction 44) -> (junction 46) : { mode = 6;  /* 垂直力が負のときの処理 垂直力、摩擦力をゼロへ */ Fn = 0; Fx = 0; Fy = 0; }
    (junction 45) -> (junction 49) : [ norm_dpt <= zvt ]
    (junction 45) -> (junction 51) : { /* 動摩擦力計算 */ Fx = -mu_d*Fn*dpx/norm_dpt; Fy = -mu_d*Fn*dpy/norm_dpt; }
    (junction 49) -> (junction 50) : { mode = 3;  /* 動摩擦力計算 */ Fx = -mu_d*Fn*dpx/zvt; Fy = -mu_d*Fn*dpy/zvt;  /* アンカーポイント設定 */ ax = px; ay = py; }
    (junction 50) -> (junction 51)
    (junction 46) -> (junction 50)
    (junction 51) -> (junction 55)
  (default) -> No_Contact
  Sliding -> No_Contact : [pn >= 0 ]
  No_Contact -> Sliding : [ pn < 0 ]
  Sticking -> No_Contact : [ pn >= 0 ]
  Sliding -> Sticking : [ pn < 0 ... && mode == 3 ]
  Sticking -> Sliding : [ pn < 0 ... && (mode == 5 || mode == 6) ]
  data: Fx output double; Fy output double; kn input =kn; kt input =kt; bn input =bn; bt input =bt; mu_d input =mu_d; mu_s input =mu_s; zvt input =zvt; px input; py input; pn input; dpx input; dpy input; Fn output double; dpn input; norm_dpt local double; norm_Ft local double; mode output double; ax local double; ay local double

== stateflow chart BipedRobot/LL0/Contact3/Contact
Force/Chart ==
  state No_Contact/
    state 非接触状態 [group]
    (default) -> (junction 48) : { mode = 1;  /* 垂直力、摩擦力ともにゼロ */ Fn = 0; Fx = 0; Fy = 0; }
  state Sticking/
    state 固着状態 [group]
    Sticking -> (junction 53) : { /* 垂直力計算 */ Fn = -(kn*pn+bn*dpn); }
    (default) -> (junction 52) : { mode = 4;  /* 垂直力計算 */ Fn = -(kn*pn+bn*dpn); }
    (junction 52) -> (junction 53)
    (junction 53) -> (junction 54) : [ Fn < 0 ]
    (junction 53) -> (junction 41) : { /* 静止摩擦力計算 */ Fx = -(kt*(px-ax)+bt*dpx); Fy = -(kt*(py-ay)+bt*dpy);  /* 摩擦力ベクトルの大きさ */ norm_Ft = sqrt(Fx^2+Fy^2); }
    (junction 54) -> (junction 47) : { mode = 6;  /* 垂直力が負のときの処理 垂直力、摩擦力をゼロへ */ Fn = 0; Fx = 0; Fy = 0; }
    (junction 41) -> (junction 40) : [ norm_Ft > mu_s*Fn ]
    (junction 41) -> (junction 39)
    (junction 40) -> (junction 38) : { mode = 5;  /* 静止摩擦力計算 */ Fx = -mu_s*Fn*Fx/norm_Ft; Fy = -mu_s*Fn*Fy/norm_Ft; }
    (junction 38) -> (junction 39)
    (junction 47) -> (junction 38)
    (junction 39) -> (junction 56)
  state Sliding/
    state 滑り状態 [group]
    Sliding -> (junction 43) : { mode = 2;  /* 垂直力計算 */ Fn = -(kn*pn+bn*dpn); }
    (default) -> (junction 42) : { mode = 2;  /* 垂直力計算 */ Fn = -(kn*pn+bn*dpn); }
    (junction 42) -> (junction 43)
    (junction 43) -> (junction 44) : [ Fn < 0 ]
    (junction 43) -> (junction 45) : { /* 接線方向速度ベクトルの大きさ */ norm_dpt = sqrt(dpx^2+dpy^2); }
    (junction 44) -> (junction 46) : { mode = 6;  /* 垂直力が負のときの処理 垂直力、摩擦力をゼロへ */ Fn = 0; Fx = 0; Fy = 0; }
    (junction 45) -> (junction 49) : [ norm_dpt <= zvt ]
    (junction 45) -> (junction 51) : { /* 動摩擦力計算 */ Fx = -mu_d*Fn*dpx/norm_dpt; Fy = -mu_d*Fn*dpy/norm_dpt; }
    (junction 49) -> (junction 50) : { mode = 3;  /* 動摩擦力計算 */ Fx = -mu_d*Fn*dpx/zvt; Fy = -mu_d*Fn*dpy/zvt;  /* アンカーポイント設定 */ ax = px; ay = py; }
    (junction 50) -> (junction 51)
    (junction 46) -> (junction 50)
    (junction 51) -> (junction 55)
  (default) -> No_Contact
  Sliding -> No_Contact : [pn >= 0 ]
  No_Contact -> Sliding : [ pn < 0 ]
  Sticking -> No_Contact : [ pn >= 0 ]
  Sliding -> Sticking : [ pn < 0 ... && mode == 3 ]
  Sticking -> Sliding : [ pn < 0 ... && (mode == 5 || mode == 6) ]
  data: Fx output double; Fy output double; kn input =kn; kt input =kt; bn input =bn; bt input =bt; mu_d input =mu_d; mu_s input =mu_s; zvt input =zvt; px input; py input; pn input; dpx input; dpy input; Fn output double; dpn input; norm_dpt local double; norm_Ft local double; mode output double; ax local double; ay local double

== stateflow chart BipedRobot/LL0/Contact4/Contact
Force/Chart ==
  state No_Contact/
    state 非接触状態 [group]
    (default) -> (junction 48) : { mode = 1;  /* 垂直力、摩擦力ともにゼロ */ Fn = 0; Fx = 0; Fy = 0; }
  state Sticking/
    state 固着状態 [group]
    Sticking -> (junction 53) : { /* 垂直力計算 */ Fn = -(kn*pn+bn*dpn); }
    (default) -> (junction 52) : { mode = 4;  /* 垂直力計算 */ Fn = -(kn*pn+bn*dpn); }
    (junction 52) -> (junction 53)
    (junction 53) -> (junction 54) : [ Fn < 0 ]
    (junction 53) -> (junction 41) : { /* 静止摩擦力計算 */ Fx = -(kt*(px-ax)+bt*dpx); Fy = -(kt*(py-ay)+bt*dpy);  /* 摩擦力ベクトルの大きさ */ norm_Ft = sqrt(Fx^2+Fy^2); }
    (junction 54) -> (junction 47) : { mode = 6;  /* 垂直力が負のときの処理 垂直力、摩擦力をゼロへ */ Fn = 0; Fx = 0; Fy = 0; }
    (junction 41) -> (junction 40) : [ norm_Ft > mu_s*Fn ]
    (junction 41) -> (junction 39)
    (junction 40) -> (junction 38) : { mode = 5;  /* 静止摩擦力計算 */ Fx = -mu_s*Fn*Fx/norm_Ft; Fy = -mu_s*Fn*Fy/norm_Ft; }
    (junction 38) -> (junction 39)
    (junction 47) -> (junction 38)
    (junction 39) -> (junction 56)
  state Sliding/
    state 滑り状態 [group]
    Sliding -> (junction 43) : { mode = 2;  /* 垂直力計算 */ Fn = -(kn*pn+bn*dpn); }
    (default) -> (junction 42) : { mode = 2;  /* 垂直力計算 */ Fn = -(kn*pn+bn*dpn); }
    (junction 42) -> (junction 43)
    (junction 43) -> (junction 44) : [ Fn < 0 ]
    (junction 43) -> (junction 45) : { /* 接線方向速度ベクトルの大きさ */ norm_dpt = sqrt(dpx^2+dpy^2); }
    (junction 44) -> (junction 46) : { mode = 6;  /* 垂直力が負のときの処理 垂直力、摩擦力をゼロへ */ Fn = 0; Fx = 0; Fy = 0; }
    (junction 45) -> (junction 49) : [ norm_dpt <= zvt ]
    (junction 45) -> (junction 51) : { /* 動摩擦力計算 */ Fx = -mu_d*Fn*dpx/norm_dpt; Fy = -mu_d*Fn*dpy/norm_dpt; }
    (junction 49) -> (junction 50) : { mode = 3;  /* 動摩擦力計算 */ Fx = -mu_d*Fn*dpx/zvt; Fy = -mu_d*Fn*dpy/zvt;  /* アンカーポイント設定 */ ax = px; ay = py; }
    (junction 50) -> (junction 51)
    (junction 46) -> (junction 50)
    (junction 51) -> (junction 55)
  (default) -> No_Contact
  Sliding -> No_Contact : [pn >= 0 ]
  No_Contact -> Sliding : [ pn < 0 ]
  Sticking -> No_Contact : [ pn >= 0 ]
  Sliding -> Sticking : [ pn < 0 ... && mode == 3 ]
  Sticking -> Sliding : [ pn < 0 ... && (mode == 5 || mode == 6) ]
  data: Fx output double; Fy output double; kn input =kn; kt input =kt; bn input =bn; bt input =bt; mu_d input =mu_d; mu_s input =mu_s; zvt input =zvt; px input; py input; pn input; dpx input; dpy input; Fn output double; dpn input; norm_dpt local double; norm_Ft local double; mode output double; ax local double; ay local double
